VERSION 5.8 ;
BUSBITCHARS "[]" ;
DIVIDERCHAR "/" ;
UNITS
    DATABASE MICRONS 1000 ;
END UNITS

VIA ino_fetch_via1_2_1000_440_1_2_410_410
  VIARULE via1Array ;
  CUTSIZE 0.19 0.19 ;
  LAYERS Metal1 Via1 Metal2 ;
  CUTSPACING 0.22 0.22 ;
  ENCLOSURE 0.05 0.125 0.005 0.05 ;
  ROWCOL 1 2 ;
END ino_fetch_via1_2_1000_440_1_2_410_410

VIA ino_fetch_via2_3_1000_440_1_2_410_410
  VIARULE via2Array ;
  CUTSIZE 0.19 0.19 ;
  LAYERS Metal2 Via2 Metal3 ;
  CUTSPACING 0.22 0.22 ;
  ENCLOSURE 0.005 0.05 0.05 0.005 ;
  ROWCOL 1 2 ;
END ino_fetch_via2_3_1000_440_1_2_410_410

VIA ino_fetch_via3_4_1000_440_1_2_410_410
  VIARULE via3Array ;
  CUTSIZE 0.19 0.19 ;
  LAYERS Metal3 Via3 Metal4 ;
  CUTSPACING 0.22 0.22 ;
  ENCLOSURE 0.05 0.005 0.2 0.05 ;
  ROWCOL 1 2 ;
END ino_fetch_via3_4_1000_440_1_2_410_410

VIA ino_fetch_via4_5_1000_2000_1_1_840_840
  VIARULE viaTop1Array ;
  CUTSIZE 0.42 0.42 ;
  LAYERS Metal4 TopVia1 TopMetal1 ;
  CUTSPACING 0.42 0.42 ;
  ENCLOSURE 0.29 0.1 0.42 0.79 ;
END ino_fetch_via4_5_1000_2000_1_1_840_840

VIA ino_fetch_via4_5_1000_1640_1_1_840_840
  VIARULE viaTop1Array ;
  CUTSIZE 0.42 0.42 ;
  LAYERS Metal4 TopVia1 TopMetal1 ;
  CUTSPACING 0.42 0.42 ;
  ENCLOSURE 0.29 0.1 0.42 0.61 ;
END ino_fetch_via4_5_1000_1640_1_1_840_840

VIA ino_fetch_via4_5_1000_1400_1_1_840_840
  VIARULE viaTop1Array ;
  CUTSIZE 0.42 0.42 ;
  LAYERS Metal4 TopVia1 TopMetal1 ;
  CUTSPACING 0.42 0.42 ;
  ENCLOSURE 0.29 0.1 0.42 0.49 ;
END ino_fetch_via4_5_1000_1400_1_1_840_840

VIA ino_fetch_via4_5_4420_2000_1_4_840_840
  VIARULE viaTop1Array ;
  CUTSIZE 0.42 0.42 ;
  LAYERS Metal4 TopVia1 TopMetal1 ;
  CUTSPACING 0.42 0.42 ;
  ENCLOSURE 0.74 0.79 0.42 0.79 ;
  ROWCOL 1 4 ;
END ino_fetch_via4_5_4420_2000_1_4_840_840

VIA ino_fetch_via4_5_2810_2000_1_2_840_840
  VIARULE viaTop1Array ;
  CUTSIZE 0.42 0.42 ;
  LAYERS Metal4 TopVia1 TopMetal1 ;
  CUTSPACING 0.42 0.42 ;
  ENCLOSURE 0.775 0.79 0.42 0.79 ;
  ROWCOL 1 2 ;
END ino_fetch_via4_5_2810_2000_1_2_840_840

VIA ino_fetch_via4_5_4420_1650_1_4_840_840
  VIARULE viaTop1Array ;
  CUTSIZE 0.42 0.42 ;
  LAYERS Metal4 TopVia1 TopMetal1 ;
  CUTSPACING 0.42 0.42 ;
  ENCLOSURE 0.74 0.615 0.42 0.615 ;
  ROWCOL 1 4 ;
END ino_fetch_via4_5_4420_1650_1_4_840_840

VIA ino_fetch_via4_5_2810_1650_1_2_840_840
  VIARULE viaTop1Array ;
  CUTSIZE 0.42 0.42 ;
  LAYERS Metal4 TopVia1 TopMetal1 ;
  CUTSPACING 0.42 0.42 ;
  ENCLOSURE 0.775 0.615 0.42 0.615 ;
  ROWCOL 1 2 ;
END ino_fetch_via4_5_2810_1650_1_2_840_840

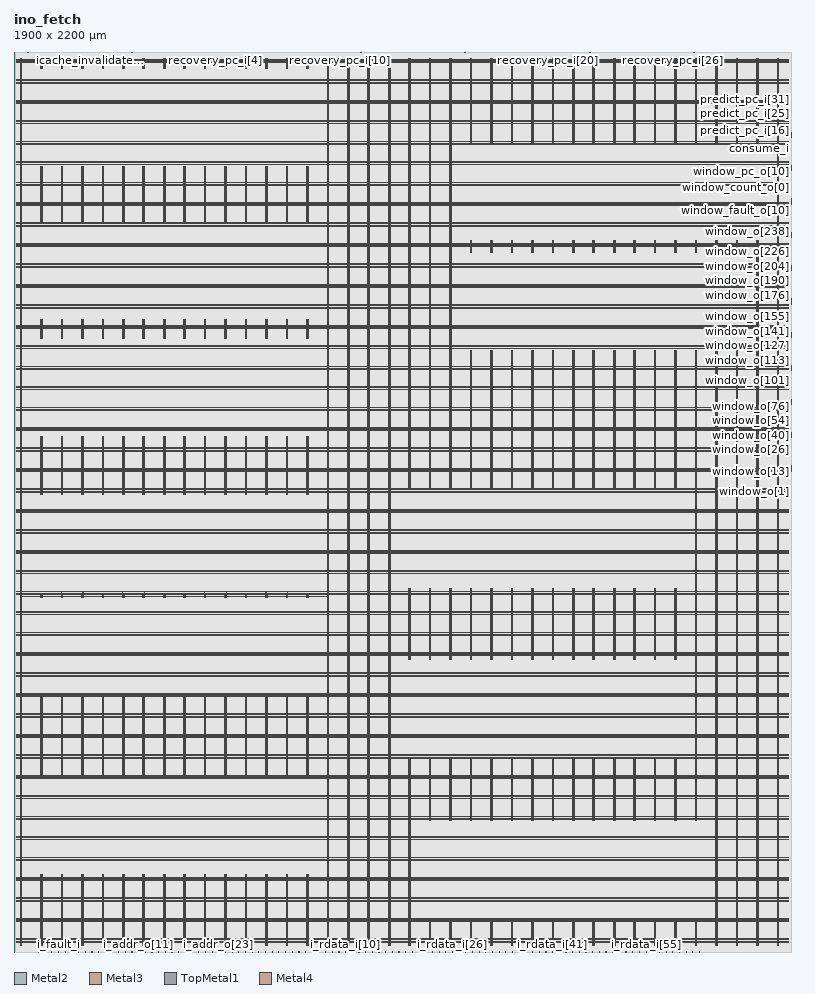
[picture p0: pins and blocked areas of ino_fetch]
MACRO ino_fetch
  FOREIGN ino_fetch 0 0 ;
  CLASS BLOCK ;
  SIZE 1900 BY 2200 ;
  PIN clk_i
    DIRECTION INPUT ;
    USE SIGNAL ;
    PORT
      LAYER Metal2 ;
        RECT  84.76 2199.6 85.16 2200 ;
    END
  END clk_i
  PIN consume_i
    DIRECTION INPUT ;
    USE SIGNAL ;
    PORT
      LAYER Metal3 ;
        RECT  1899.6 1964.14 1900 1964.54 ;
    END
  END consume_i
  PIN consumed_bytes_i[0]
    DIRECTION INPUT ;
    USE SIGNAL ;
    PORT
      LAYER Metal3 ;
        RECT  1899.6 1966.66 1900 1967.06 ;
    END
  END consumed_bytes_i[0]
  PIN consumed_bytes_i[1]
    DIRECTION INPUT ;
    USE SIGNAL ;
    PORT
      LAYER Metal3 ;
        RECT  1899.6 1969.18 1900 1969.58 ;
    END
  END consumed_bytes_i[1]
  PIN consumed_bytes_i[2]
    DIRECTION INPUT ;
    USE SIGNAL ;
    PORT
      LAYER Metal3 ;
        RECT  1899.6 1971.7 1900 1972.1 ;
    END
  END consumed_bytes_i[2]
  PIN consumed_bytes_i[3]
    DIRECTION INPUT ;
    USE SIGNAL ;
    PORT
      LAYER Metal3 ;
        RECT  1899.6 1974.22 1900 1974.62 ;
    END
  END consumed_bytes_i[3]
  PIN consumed_bytes_i[4]
    DIRECTION INPUT ;
    USE SIGNAL ;
    PORT
      LAYER Metal3 ;
        RECT  1899.6 1976.74 1900 1977.14 ;
    END
  END consumed_bytes_i[4]
  PIN consumed_bytes_i[5]
    DIRECTION INPUT ;
    USE SIGNAL ;
    PORT
      LAYER Metal3 ;
        RECT  1899.6 1979.26 1900 1979.66 ;
    END
  END consumed_bytes_i[5]
  PIN decode_stop_i
    DIRECTION INPUT ;
    USE SIGNAL ;
    PORT
      LAYER Metal3 ;
        RECT  1899.6 1981.78 1900 1982.18 ;
    END
  END decode_stop_i
  PIN halt_i
    DIRECTION INPUT ;
    USE SIGNAL ;
    PORT
      LAYER Metal2 ;
        RECT  135.64 2199.6 136.04 2200 ;
    END
  END halt_i
  PIN i_addr_o[0]
    DIRECTION OUTPUT ;
    USE SIGNAL ;
    PORT
      LAYER Metal2 ;
        RECT  125.08 0 125.48 0.4 ;
    END
  END i_addr_o[0]
  PIN i_addr_o[10]
    DIRECTION OUTPUT ;
    USE SIGNAL ;
    PORT
      LAYER Metal2 ;
        RECT  288.28 0 288.68 0.4 ;
    END
  END i_addr_o[10]
  PIN i_addr_o[11]
    DIRECTION OUTPUT ;
    USE SIGNAL ;
    PORT
      LAYER Metal2 ;
        RECT  304.6 0 305 0.4 ;
    END
  END i_addr_o[11]
  PIN i_addr_o[12]
    DIRECTION OUTPUT ;
    USE SIGNAL ;
    PORT
      LAYER Metal2 ;
        RECT  320.92 0 321.32 0.4 ;
    END
  END i_addr_o[12]
  PIN i_addr_o[13]
    DIRECTION OUTPUT ;
    USE SIGNAL ;
    PORT
      LAYER Metal2 ;
        RECT  337.24 0 337.64 0.4 ;
    END
  END i_addr_o[13]
  PIN i_addr_o[14]
    DIRECTION OUTPUT ;
    USE SIGNAL ;
    PORT
      LAYER Metal2 ;
        RECT  353.56 0 353.96 0.4 ;
    END
  END i_addr_o[14]
  PIN i_addr_o[15]
    DIRECTION OUTPUT ;
    USE SIGNAL ;
    PORT
      LAYER Metal2 ;
        RECT  369.88 0 370.28 0.4 ;
    END
  END i_addr_o[15]
  PIN i_addr_o[16]
    DIRECTION OUTPUT ;
    USE SIGNAL ;
    PORT
      LAYER Metal2 ;
        RECT  386.2 0 386.6 0.4 ;
    END
  END i_addr_o[16]
  PIN i_addr_o[17]
    DIRECTION OUTPUT ;
    USE SIGNAL ;
    PORT
      LAYER Metal2 ;
        RECT  402.52 0 402.92 0.4 ;
    END
  END i_addr_o[17]
  PIN i_addr_o[18]
    DIRECTION OUTPUT ;
    USE SIGNAL ;
    PORT
      LAYER Metal2 ;
        RECT  418.84 0 419.24 0.4 ;
    END
  END i_addr_o[18]
  PIN i_addr_o[19]
    DIRECTION OUTPUT ;
    USE SIGNAL ;
    PORT
      LAYER Metal2 ;
        RECT  435.16 0 435.56 0.4 ;
    END
  END i_addr_o[19]
  PIN i_addr_o[1]
    DIRECTION OUTPUT ;
    USE SIGNAL ;
    PORT
      LAYER Metal2 ;
        RECT  141.4 0 141.8 0.4 ;
    END
  END i_addr_o[1]
  PIN i_addr_o[20]
    DIRECTION OUTPUT ;
    USE SIGNAL ;
    PORT
      LAYER Metal2 ;
        RECT  451.48 0 451.88 0.4 ;
    END
  END i_addr_o[20]
  PIN i_addr_o[21]
    DIRECTION OUTPUT ;
    USE SIGNAL ;
    PORT
      LAYER Metal2 ;
        RECT  467.8 0 468.2 0.4 ;
    END
  END i_addr_o[21]
  PIN i_addr_o[22]
    DIRECTION OUTPUT ;
    USE SIGNAL ;
    PORT
      LAYER Metal2 ;
        RECT  484.12 0 484.52 0.4 ;
    END
  END i_addr_o[22]
  PIN i_addr_o[23]
    DIRECTION OUTPUT ;
    USE SIGNAL ;
    PORT
      LAYER Metal2 ;
        RECT  500.44 0 500.84 0.4 ;
    END
  END i_addr_o[23]
  PIN i_addr_o[24]
    DIRECTION OUTPUT ;
    USE SIGNAL ;
    PORT
      LAYER Metal2 ;
        RECT  516.76 0 517.16 0.4 ;
    END
  END i_addr_o[24]
  PIN i_addr_o[25]
    DIRECTION OUTPUT ;
    USE SIGNAL ;
    PORT
      LAYER Metal2 ;
        RECT  533.08 0 533.48 0.4 ;
    END
  END i_addr_o[25]
  PIN i_addr_o[26]
    DIRECTION OUTPUT ;
    USE SIGNAL ;
    PORT
      LAYER Metal2 ;
        RECT  549.4 0 549.8 0.4 ;
    END
  END i_addr_o[26]
  PIN i_addr_o[27]
    DIRECTION OUTPUT ;
    USE SIGNAL ;
    PORT
      LAYER Metal2 ;
        RECT  565.72 0 566.12 0.4 ;
    END
  END i_addr_o[27]
  PIN i_addr_o[28]
    DIRECTION OUTPUT ;
    USE SIGNAL ;
    PORT
      LAYER Metal2 ;
        RECT  582.04 0 582.44 0.4 ;
    END
  END i_addr_o[28]
  PIN i_addr_o[29]
    DIRECTION OUTPUT ;
    USE SIGNAL ;
    PORT
      LAYER Metal2 ;
        RECT  598.36 0 598.76 0.4 ;
    END
  END i_addr_o[29]
  PIN i_addr_o[2]
    DIRECTION OUTPUT ;
    USE SIGNAL ;
    PORT
      LAYER Metal2 ;
        RECT  157.72 0 158.12 0.4 ;
    END
  END i_addr_o[2]
  PIN i_addr_o[30]
    DIRECTION OUTPUT ;
    USE SIGNAL ;
    PORT
      LAYER Metal2 ;
        RECT  614.68 0 615.08 0.4 ;
    END
  END i_addr_o[30]
  PIN i_addr_o[31]
    DIRECTION OUTPUT ;
    USE SIGNAL ;
    PORT
      LAYER Metal2 ;
        RECT  631 0 631.4 0.4 ;
    END
  END i_addr_o[31]
  PIN i_addr_o[3]
    DIRECTION OUTPUT ;
    USE SIGNAL ;
    PORT
      LAYER Metal2 ;
        RECT  174.04 0 174.44 0.4 ;
    END
  END i_addr_o[3]
  PIN i_addr_o[4]
    DIRECTION OUTPUT ;
    USE SIGNAL ;
    PORT
      LAYER Metal2 ;
        RECT  190.36 0 190.76 0.4 ;
    END
  END i_addr_o[4]
  PIN i_addr_o[5]
    DIRECTION OUTPUT ;
    USE SIGNAL ;
    PORT
      LAYER Metal2 ;
        RECT  206.68 0 207.08 0.4 ;
    END
  END i_addr_o[5]
  PIN i_addr_o[6]
    DIRECTION OUTPUT ;
    USE SIGNAL ;
    PORT
      LAYER Metal2 ;
        RECT  223 0 223.4 0.4 ;
    END
  END i_addr_o[6]
  PIN i_addr_o[7]
    DIRECTION OUTPUT ;
    USE SIGNAL ;
    PORT
      LAYER Metal2 ;
        RECT  239.32 0 239.72 0.4 ;
    END
  END i_addr_o[7]
  PIN i_addr_o[8]
    DIRECTION OUTPUT ;
    USE SIGNAL ;
    PORT
      LAYER Metal2 ;
        RECT  255.64 0 256.04 0.4 ;
    END
  END i_addr_o[8]
  PIN i_addr_o[9]
    DIRECTION OUTPUT ;
    USE SIGNAL ;
    PORT
      LAYER Metal2 ;
        RECT  271.96 0 272.36 0.4 ;
    END
  END i_addr_o[9]
  PIN i_fault_i
    DIRECTION INPUT ;
    USE SIGNAL ;
    PORT
      LAYER Metal2 ;
        RECT  108.76 0 109.16 0.4 ;
    END
  END i_fault_i
  PIN i_rdata_i[0]
    DIRECTION INPUT ;
    USE SIGNAL ;
    PORT
      LAYER Metal2 ;
        RECT  647.32 0 647.72 0.4 ;
    END
  END i_rdata_i[0]
  PIN i_rdata_i[10]
    DIRECTION INPUT ;
    USE SIGNAL ;
    PORT
      LAYER Metal2 ;
        RECT  810.52 0 810.92 0.4 ;
    END
  END i_rdata_i[10]
  PIN i_rdata_i[11]
    DIRECTION INPUT ;
    USE SIGNAL ;
    PORT
      LAYER Metal2 ;
        RECT  826.84 0 827.24 0.4 ;
    END
  END i_rdata_i[11]
  PIN i_rdata_i[12]
    DIRECTION INPUT ;
    USE SIGNAL ;
    PORT
      LAYER Metal2 ;
        RECT  843.16 0 843.56 0.4 ;
    END
  END i_rdata_i[12]
  PIN i_rdata_i[13]
    DIRECTION INPUT ;
    USE SIGNAL ;
    PORT
      LAYER Metal2 ;
        RECT  859.48 0 859.88 0.4 ;
    END
  END i_rdata_i[13]
  PIN i_rdata_i[14]
    DIRECTION INPUT ;
    USE SIGNAL ;
    PORT
      LAYER Metal2 ;
        RECT  875.8 0 876.2 0.4 ;
    END
  END i_rdata_i[14]
  PIN i_rdata_i[15]
    DIRECTION INPUT ;
    USE SIGNAL ;
    PORT
      LAYER Metal2 ;
        RECT  892.12 0 892.52 0.4 ;
    END
  END i_rdata_i[15]
  PIN i_rdata_i[16]
    DIRECTION INPUT ;
    USE SIGNAL ;
    PORT
      LAYER Metal2 ;
        RECT  908.44 0 908.84 0.4 ;
    END
  END i_rdata_i[16]
  PIN i_rdata_i[17]
    DIRECTION INPUT ;
    USE SIGNAL ;
    PORT
      LAYER Metal2 ;
        RECT  924.76 0 925.16 0.4 ;
    END
  END i_rdata_i[17]
  PIN i_rdata_i[18]
    DIRECTION INPUT ;
    USE SIGNAL ;
    PORT
      LAYER Metal2 ;
        RECT  941.08 0 941.48 0.4 ;
    END
  END i_rdata_i[18]
  PIN i_rdata_i[19]
    DIRECTION INPUT ;
    USE SIGNAL ;
    PORT
      LAYER Metal2 ;
        RECT  957.4 0 957.8 0.4 ;
    END
  END i_rdata_i[19]
  PIN i_rdata_i[1]
    DIRECTION INPUT ;
    USE SIGNAL ;
    PORT
      LAYER Metal2 ;
        RECT  663.64 0 664.04 0.4 ;
    END
  END i_rdata_i[1]
  PIN i_rdata_i[20]
    DIRECTION INPUT ;
    USE SIGNAL ;
    PORT
      LAYER Metal2 ;
        RECT  973.72 0 974.12 0.4 ;
    END
  END i_rdata_i[20]
  PIN i_rdata_i[21]
    DIRECTION INPUT ;
    USE SIGNAL ;
    PORT
      LAYER Metal2 ;
        RECT  990.04 0 990.44 0.4 ;
    END
  END i_rdata_i[21]
  PIN i_rdata_i[22]
    DIRECTION INPUT ;
    USE SIGNAL ;
    PORT
      LAYER Metal2 ;
        RECT  1006.36 0 1006.76 0.4 ;
    END
  END i_rdata_i[22]
  PIN i_rdata_i[23]
    DIRECTION INPUT ;
    USE SIGNAL ;
    PORT
      LAYER Metal2 ;
        RECT  1022.68 0 1023.08 0.4 ;
    END
  END i_rdata_i[23]
  PIN i_rdata_i[24]
    DIRECTION INPUT ;
    USE SIGNAL ;
    PORT
      LAYER Metal2 ;
        RECT  1039 0 1039.4 0.4 ;
    END
  END i_rdata_i[24]
  PIN i_rdata_i[25]
    DIRECTION INPUT ;
    USE SIGNAL ;
    PORT
      LAYER Metal2 ;
        RECT  1055.32 0 1055.72 0.4 ;
    END
  END i_rdata_i[25]
  PIN i_rdata_i[26]
    DIRECTION INPUT ;
    USE SIGNAL ;
    PORT
      LAYER Metal2 ;
        RECT  1071.64 0 1072.04 0.4 ;
    END
  END i_rdata_i[26]
  PIN i_rdata_i[27]
    DIRECTION INPUT ;
    USE SIGNAL ;
    PORT
      LAYER Metal2 ;
        RECT  1087.96 0 1088.36 0.4 ;
    END
  END i_rdata_i[27]
  PIN i_rdata_i[28]
    DIRECTION INPUT ;
    USE SIGNAL ;
    PORT
      LAYER Metal2 ;
        RECT  1104.28 0 1104.68 0.4 ;
    END
  END i_rdata_i[28]
  PIN i_rdata_i[29]
    DIRECTION INPUT ;
    USE SIGNAL ;
    PORT
      LAYER Metal2 ;
        RECT  1120.6 0 1121 0.4 ;
    END
  END i_rdata_i[29]
  PIN i_rdata_i[2]
    DIRECTION INPUT ;
    USE SIGNAL ;
    PORT
      LAYER Metal2 ;
        RECT  679.96 0 680.36 0.4 ;
    END
  END i_rdata_i[2]
  PIN i_rdata_i[30]
    DIRECTION INPUT ;
    USE SIGNAL ;
    PORT
      LAYER Metal2 ;
        RECT  1136.92 0 1137.32 0.4 ;
    END
  END i_rdata_i[30]
  PIN i_rdata_i[31]
    DIRECTION INPUT ;
    USE SIGNAL ;
    PORT
      LAYER Metal2 ;
        RECT  1153.24 0 1153.64 0.4 ;
    END
  END i_rdata_i[31]
  PIN i_rdata_i[32]
    DIRECTION INPUT ;
    USE SIGNAL ;
    PORT
      LAYER Metal2 ;
        RECT  1169.56 0 1169.96 0.4 ;
    END
  END i_rdata_i[32]
  PIN i_rdata_i[33]
    DIRECTION INPUT ;
    USE SIGNAL ;
    PORT
      LAYER Metal2 ;
        RECT  1185.88 0 1186.28 0.4 ;
    END
  END i_rdata_i[33]
  PIN i_rdata_i[34]
    DIRECTION INPUT ;
    USE SIGNAL ;
    PORT
      LAYER Metal2 ;
        RECT  1202.2 0 1202.6 0.4 ;
    END
  END i_rdata_i[34]
  PIN i_rdata_i[35]
    DIRECTION INPUT ;
    USE SIGNAL ;
    PORT
      LAYER Metal2 ;
        RECT  1218.52 0 1218.92 0.4 ;
    END
  END i_rdata_i[35]
  PIN i_rdata_i[36]
    DIRECTION INPUT ;
    USE SIGNAL ;
    PORT
      LAYER Metal2 ;
        RECT  1234.84 0 1235.24 0.4 ;
    END
  END i_rdata_i[36]
  PIN i_rdata_i[37]
    DIRECTION INPUT ;
    USE SIGNAL ;
    PORT
      LAYER Metal2 ;
        RECT  1251.16 0 1251.56 0.4 ;
    END
  END i_rdata_i[37]
  PIN i_rdata_i[38]
    DIRECTION INPUT ;
    USE SIGNAL ;
    PORT
      LAYER Metal2 ;
        RECT  1267.48 0 1267.88 0.4 ;
    END
  END i_rdata_i[38]
  PIN i_rdata_i[39]
    DIRECTION INPUT ;
    USE SIGNAL ;
    PORT
      LAYER Metal2 ;
        RECT  1283.8 0 1284.2 0.4 ;
    END
  END i_rdata_i[39]
  PIN i_rdata_i[3]
    DIRECTION INPUT ;
    USE SIGNAL ;
    PORT
      LAYER Metal2 ;
        RECT  696.28 0 696.68 0.4 ;
    END
  END i_rdata_i[3]
  PIN i_rdata_i[40]
    DIRECTION INPUT ;
    USE SIGNAL ;
    PORT
      LAYER Metal2 ;
        RECT  1300.12 0 1300.52 0.4 ;
    END
  END i_rdata_i[40]
  PIN i_rdata_i[41]
    DIRECTION INPUT ;
    USE SIGNAL ;
    PORT
      LAYER Metal2 ;
        RECT  1316.44 0 1316.84 0.4 ;
    END
  END i_rdata_i[41]
  PIN i_rdata_i[42]
    DIRECTION INPUT ;
    USE SIGNAL ;
    PORT
      LAYER Metal2 ;
        RECT  1332.76 0 1333.16 0.4 ;
    END
  END i_rdata_i[42]
  PIN i_rdata_i[43]
    DIRECTION INPUT ;
    USE SIGNAL ;
    PORT
      LAYER Metal2 ;
        RECT  1349.08 0 1349.48 0.4 ;
    END
  END i_rdata_i[43]
  PIN i_rdata_i[44]
    DIRECTION INPUT ;
    USE SIGNAL ;
    PORT
      LAYER Metal2 ;
        RECT  1365.4 0 1365.8 0.4 ;
    END
  END i_rdata_i[44]
  PIN i_rdata_i[45]
    DIRECTION INPUT ;
    USE SIGNAL ;
    PORT
      LAYER Metal2 ;
        RECT  1381.72 0 1382.12 0.4 ;
    END
  END i_rdata_i[45]
  PIN i_rdata_i[46]
    DIRECTION INPUT ;
    USE SIGNAL ;
    PORT
      LAYER Metal2 ;
        RECT  1398.04 0 1398.44 0.4 ;
    END
  END i_rdata_i[46]
  PIN i_rdata_i[47]
    DIRECTION INPUT ;
    USE SIGNAL ;
    PORT
      LAYER Metal2 ;
        RECT  1414.36 0 1414.76 0.4 ;
    END
  END i_rdata_i[47]
  PIN i_rdata_i[48]
    DIRECTION INPUT ;
    USE SIGNAL ;
    PORT
      LAYER Metal2 ;
        RECT  1430.68 0 1431.08 0.4 ;
    END
  END i_rdata_i[48]
  PIN i_rdata_i[49]
    DIRECTION INPUT ;
    USE SIGNAL ;
    PORT
      LAYER Metal2 ;
        RECT  1447 0 1447.4 0.4 ;
    END
  END i_rdata_i[49]
  PIN i_rdata_i[4]
    DIRECTION INPUT ;
    USE SIGNAL ;
    PORT
      LAYER Metal2 ;
        RECT  712.6 0 713 0.4 ;
    END
  END i_rdata_i[4]
  PIN i_rdata_i[50]
    DIRECTION INPUT ;
    USE SIGNAL ;
    PORT
      LAYER Metal2 ;
        RECT  1463.32 0 1463.72 0.4 ;
    END
  END i_rdata_i[50]
  PIN i_rdata_i[51]
    DIRECTION INPUT ;
    USE SIGNAL ;
    PORT
      LAYER Metal2 ;
        RECT  1479.64 0 1480.04 0.4 ;
    END
  END i_rdata_i[51]
  PIN i_rdata_i[52]
    DIRECTION INPUT ;
    USE SIGNAL ;
    PORT
      LAYER Metal2 ;
        RECT  1495.96 0 1496.36 0.4 ;
    END
  END i_rdata_i[52]
  PIN i_rdata_i[53]
    DIRECTION INPUT ;
    USE SIGNAL ;
    PORT
      LAYER Metal2 ;
        RECT  1512.28 0 1512.68 0.4 ;
    END
  END i_rdata_i[53]
  PIN i_rdata_i[54]
    DIRECTION INPUT ;
    USE SIGNAL ;
    PORT
      LAYER Metal2 ;
        RECT  1528.6 0 1529 0.4 ;
    END
  END i_rdata_i[54]
  PIN i_rdata_i[55]
    DIRECTION INPUT ;
    USE SIGNAL ;
    PORT
      LAYER Metal2 ;
        RECT  1544.92 0 1545.32 0.4 ;
    END
  END i_rdata_i[55]
  PIN i_rdata_i[56]
    DIRECTION INPUT ;
    USE SIGNAL ;
    PORT
      LAYER Metal2 ;
        RECT  1561.24 0 1561.64 0.4 ;
    END
  END i_rdata_i[56]
  PIN i_rdata_i[57]
    DIRECTION INPUT ;
    USE SIGNAL ;
    PORT
      LAYER Metal2 ;
        RECT  1577.56 0 1577.96 0.4 ;
    END
  END i_rdata_i[57]
  PIN i_rdata_i[58]
    DIRECTION INPUT ;
    USE SIGNAL ;
    PORT
      LAYER Metal2 ;
        RECT  1593.88 0 1594.28 0.4 ;
    END
  END i_rdata_i[58]
  PIN i_rdata_i[59]
    DIRECTION INPUT ;
    USE SIGNAL ;
    PORT
      LAYER Metal2 ;
        RECT  1610.2 0 1610.6 0.4 ;
    END
  END i_rdata_i[59]
  PIN i_rdata_i[5]
    DIRECTION INPUT ;
    USE SIGNAL ;
    PORT
      LAYER Metal2 ;
        RECT  728.92 0 729.32 0.4 ;
    END
  END i_rdata_i[5]
  PIN i_rdata_i[60]
    DIRECTION INPUT ;
    USE SIGNAL ;
    PORT
      LAYER Metal2 ;
        RECT  1626.52 0 1626.92 0.4 ;
    END
  END i_rdata_i[60]
  PIN i_rdata_i[61]
    DIRECTION INPUT ;
    USE SIGNAL ;
    PORT
      LAYER Metal2 ;
        RECT  1642.84 0 1643.24 0.4 ;
    END
  END i_rdata_i[61]
  PIN i_rdata_i[62]
    DIRECTION INPUT ;
    USE SIGNAL ;
    PORT
      LAYER Metal2 ;
        RECT  1659.16 0 1659.56 0.4 ;
    END
  END i_rdata_i[62]
  PIN i_rdata_i[63]
    DIRECTION INPUT ;
    USE SIGNAL ;
    PORT
      LAYER Metal2 ;
        RECT  1675.48 0 1675.88 0.4 ;
    END
  END i_rdata_i[63]
  PIN i_rdata_i[6]
    DIRECTION INPUT ;
    USE SIGNAL ;
    PORT
      LAYER Metal2 ;
        RECT  745.24 0 745.64 0.4 ;
    END
  END i_rdata_i[6]
  PIN i_rdata_i[7]
    DIRECTION INPUT ;
    USE SIGNAL ;
    PORT
      LAYER Metal2 ;
        RECT  761.56 0 761.96 0.4 ;
    END
  END i_rdata_i[7]
  PIN i_rdata_i[8]
    DIRECTION INPUT ;
    USE SIGNAL ;
    PORT
      LAYER Metal2 ;
        RECT  777.88 0 778.28 0.4 ;
    END
  END i_rdata_i[8]
  PIN i_rdata_i[9]
    DIRECTION INPUT ;
    USE SIGNAL ;
    PORT
      LAYER Metal2 ;
        RECT  794.2 0 794.6 0.4 ;
    END
  END i_rdata_i[9]
  PIN i_ready_i
    DIRECTION INPUT ;
    USE SIGNAL ;
    PORT
      LAYER Metal2 ;
        RECT  76.12 0 76.52 0.4 ;
    END
  END i_ready_i
  PIN i_req_o
    DIRECTION OUTPUT ;
    USE SIGNAL ;
    PORT
      LAYER Metal2 ;
        RECT  59.8 0 60.2 0.4 ;
    END
  END i_req_o
  PIN i_rvalid_i
    DIRECTION INPUT ;
    USE SIGNAL ;
    PORT
      LAYER Metal2 ;
        RECT  92.44 0 92.84 0.4 ;
    END
  END i_rvalid_i
  PIN icache_invalidate_i
    DIRECTION INPUT ;
    USE SIGNAL ;
    PORT
      LAYER Metal2 ;
        RECT  186.52 2199.6 186.92 2200 ;
    END
  END icache_invalidate_i
  PIN predict_pc_i[0]
    DIRECTION INPUT ;
    USE SIGNAL ;
    PORT
      LAYER Metal3 ;
        RECT  1899.6 1986.82 1900 1987.22 ;
    END
  END predict_pc_i[0]
  PIN predict_pc_i[10]
    DIRECTION INPUT ;
    USE SIGNAL ;
    PORT
      LAYER Metal3 ;
        RECT  1899.6 2012.02 1900 2012.42 ;
    END
  END predict_pc_i[10]
  PIN predict_pc_i[11]
    DIRECTION INPUT ;
    USE SIGNAL ;
    PORT
      LAYER Metal3 ;
        RECT  1899.6 2014.54 1900 2014.94 ;
    END
  END predict_pc_i[11]
  PIN predict_pc_i[12]
    DIRECTION INPUT ;
    USE SIGNAL ;
    PORT
      LAYER Metal3 ;
        RECT  1899.6 2017.06 1900 2017.46 ;
    END
  END predict_pc_i[12]
  PIN predict_pc_i[13]
    DIRECTION INPUT ;
    USE SIGNAL ;
    PORT
      LAYER Metal3 ;
        RECT  1899.6 2019.58 1900 2019.98 ;
    END
  END predict_pc_i[13]
  PIN predict_pc_i[14]
    DIRECTION INPUT ;
    USE SIGNAL ;
    PORT
      LAYER Metal3 ;
        RECT  1899.6 2022.1 1900 2022.5 ;
    END
  END predict_pc_i[14]
  PIN predict_pc_i[15]
    DIRECTION INPUT ;
    USE SIGNAL ;
    PORT
      LAYER Metal3 ;
        RECT  1899.6 2024.62 1900 2025.02 ;
    END
  END predict_pc_i[15]
  PIN predict_pc_i[16]
    DIRECTION INPUT ;
    USE SIGNAL ;
    PORT
      LAYER Metal3 ;
        RECT  1899.6 2027.14 1900 2027.54 ;
    END
  END predict_pc_i[16]
  PIN predict_pc_i[17]
    DIRECTION INPUT ;
    USE SIGNAL ;
    PORT
      LAYER Metal3 ;
        RECT  1899.6 2029.66 1900 2030.06 ;
    END
  END predict_pc_i[17]
  PIN predict_pc_i[18]
    DIRECTION INPUT ;
    USE SIGNAL ;
    PORT
      LAYER Metal3 ;
        RECT  1899.6 2032.18 1900 2032.58 ;
    END
  END predict_pc_i[18]
  PIN predict_pc_i[19]
    DIRECTION INPUT ;
    USE SIGNAL ;
    PORT
      LAYER Metal3 ;
        RECT  1899.6 2034.7 1900 2035.1 ;
    END
  END predict_pc_i[19]
  PIN predict_pc_i[1]
    DIRECTION INPUT ;
    USE SIGNAL ;
    PORT
      LAYER Metal3 ;
        RECT  1899.6 1989.34 1900 1989.74 ;
    END
  END predict_pc_i[1]
  PIN predict_pc_i[20]
    DIRECTION INPUT ;
    USE SIGNAL ;
    PORT
      LAYER Metal3 ;
        RECT  1899.6 2037.22 1900 2037.62 ;
    END
  END predict_pc_i[20]
  PIN predict_pc_i[21]
    DIRECTION INPUT ;
    USE SIGNAL ;
    PORT
      LAYER Metal3 ;
        RECT  1899.6 2039.74 1900 2040.14 ;
    END
  END predict_pc_i[21]
  PIN predict_pc_i[22]
    DIRECTION INPUT ;
    USE SIGNAL ;
    PORT
      LAYER Metal3 ;
        RECT  1899.6 2042.26 1900 2042.66 ;
    END
  END predict_pc_i[22]
  PIN predict_pc_i[23]
    DIRECTION INPUT ;
    USE SIGNAL ;
    PORT
      LAYER Metal3 ;
        RECT  1899.6 2044.78 1900 2045.18 ;
    END
  END predict_pc_i[23]
  PIN predict_pc_i[24]
    DIRECTION INPUT ;
    USE SIGNAL ;
    PORT
      LAYER Metal3 ;
        RECT  1899.6 2047.3 1900 2047.7 ;
    END
  END predict_pc_i[24]
  PIN predict_pc_i[25]
    DIRECTION INPUT ;
    USE SIGNAL ;
    PORT
      LAYER Metal3 ;
        RECT  1899.6 2049.82 1900 2050.22 ;
    END
  END predict_pc_i[25]
  PIN predict_pc_i[26]
    DIRECTION INPUT ;
    USE SIGNAL ;
    PORT
      LAYER Metal3 ;
        RECT  1899.6 2052.34 1900 2052.74 ;
    END
  END predict_pc_i[26]
  PIN predict_pc_i[27]
    DIRECTION INPUT ;
    USE SIGNAL ;
    PORT
      LAYER Metal3 ;
        RECT  1899.6 2054.86 1900 2055.26 ;
    END
  END predict_pc_i[27]
  PIN predict_pc_i[28]
    DIRECTION INPUT ;
    USE SIGNAL ;
    PORT
      LAYER Metal3 ;
        RECT  1899.6 2057.38 1900 2057.78 ;
    END
  END predict_pc_i[28]
  PIN predict_pc_i[29]
    DIRECTION INPUT ;
    USE SIGNAL ;
    PORT
      LAYER Metal3 ;
        RECT  1899.6 2059.9 1900 2060.3 ;
    END
  END predict_pc_i[29]
  PIN predict_pc_i[2]
    DIRECTION INPUT ;
    USE SIGNAL ;
    PORT
      LAYER Metal3 ;
        RECT  1899.6 1991.86 1900 1992.26 ;
    END
  END predict_pc_i[2]
  PIN predict_pc_i[30]
    DIRECTION INPUT ;
    USE SIGNAL ;
    PORT
      LAYER Metal3 ;
        RECT  1899.6 2062.42 1900 2062.82 ;
    END
  END predict_pc_i[30]
  PIN predict_pc_i[31]
    DIRECTION INPUT ;
    USE SIGNAL ;
    PORT
      LAYER Metal3 ;
        RECT  1899.6 2064.94 1900 2065.34 ;
    END
  END predict_pc_i[31]
  PIN predict_pc_i[3]
    DIRECTION INPUT ;
    USE SIGNAL ;
    PORT
      LAYER Metal3 ;
        RECT  1899.6 1994.38 1900 1994.78 ;
    END
  END predict_pc_i[3]
  PIN predict_pc_i[4]
    DIRECTION INPUT ;
    USE SIGNAL ;
    PORT
      LAYER Metal3 ;
        RECT  1899.6 1996.9 1900 1997.3 ;
    END
  END predict_pc_i[4]
  PIN predict_pc_i[5]
    DIRECTION INPUT ;
    USE SIGNAL ;
    PORT
      LAYER Metal3 ;
        RECT  1899.6 1999.42 1900 1999.82 ;
    END
  END predict_pc_i[5]
  PIN predict_pc_i[6]
    DIRECTION INPUT ;
    USE SIGNAL ;
    PORT
      LAYER Metal3 ;
        RECT  1899.6 2001.94 1900 2002.34 ;
    END
  END predict_pc_i[6]
  PIN predict_pc_i[7]
    DIRECTION INPUT ;
    USE SIGNAL ;
    PORT
      LAYER Metal3 ;
        RECT  1899.6 2004.46 1900 2004.86 ;
    END
  END predict_pc_i[7]
  PIN predict_pc_i[8]
    DIRECTION INPUT ;
    USE SIGNAL ;
    PORT
      LAYER Metal3 ;
        RECT  1899.6 2006.98 1900 2007.38 ;
    END
  END predict_pc_i[8]
  PIN predict_pc_i[9]
    DIRECTION INPUT ;
    USE SIGNAL ;
    PORT
      LAYER Metal3 ;
        RECT  1899.6 2009.5 1900 2009.9 ;
    END
  END predict_pc_i[9]
  PIN predict_valid_i
    DIRECTION INPUT ;
    USE SIGNAL ;
    PORT
      LAYER Metal3 ;
        RECT  1899.6 1984.3 1900 1984.7 ;
    END
  END predict_valid_i
  PIN recovery_pc_i[0]
    DIRECTION INPUT ;
    USE SIGNAL ;
    PORT
      LAYER Metal2 ;
        RECT  288.28 2199.6 288.68 2200 ;
    END
  END recovery_pc_i[0]
  PIN recovery_pc_i[10]
    DIRECTION INPUT ;
    USE SIGNAL ;
    PORT
      LAYER Metal2 ;
        RECT  797.08 2199.6 797.48 2200 ;
    END
  END recovery_pc_i[10]
  PIN recovery_pc_i[11]
    DIRECTION INPUT ;
    USE SIGNAL ;
    PORT
      LAYER Metal2 ;
        RECT  847.96 2199.6 848.36 2200 ;
    END
  END recovery_pc_i[11]
  PIN recovery_pc_i[12]
    DIRECTION INPUT ;
    USE SIGNAL ;
    PORT
      LAYER Metal2 ;
        RECT  898.84 2199.6 899.24 2200 ;
    END
  END recovery_pc_i[12]
  PIN recovery_pc_i[13]
    DIRECTION INPUT ;
    USE SIGNAL ;
    PORT
      LAYER Metal2 ;
        RECT  949.72 2199.6 950.12 2200 ;
    END
  END recovery_pc_i[13]
  PIN recovery_pc_i[14]
    DIRECTION INPUT ;
    USE SIGNAL ;
    PORT
      LAYER Metal2 ;
        RECT  1000.6 2199.6 1001 2200 ;
    END
  END recovery_pc_i[14]
  PIN recovery_pc_i[15]
    DIRECTION INPUT ;
    USE SIGNAL ;
    PORT
      LAYER Metal2 ;
        RECT  1051.48 2199.6 1051.88 2200 ;
    END
  END recovery_pc_i[15]
  PIN recovery_pc_i[16]
    DIRECTION INPUT ;
    USE SIGNAL ;
    PORT
      LAYER Metal2 ;
        RECT  1102.36 2199.6 1102.76 2200 ;
    END
  END recovery_pc_i[16]
  PIN recovery_pc_i[17]
    DIRECTION INPUT ;
    USE SIGNAL ;
    PORT
      LAYER Metal2 ;
        RECT  1153.24 2199.6 1153.64 2200 ;
    END
  END recovery_pc_i[17]
  PIN recovery_pc_i[18]
    DIRECTION INPUT ;
    USE SIGNAL ;
    PORT
      LAYER Metal2 ;
        RECT  1204.12 2199.6 1204.52 2200 ;
    END
  END recovery_pc_i[18]
  PIN recovery_pc_i[19]
    DIRECTION INPUT ;
    USE SIGNAL ;
    PORT
      LAYER Metal2 ;
        RECT  1255 2199.6 1255.4 2200 ;
    END
  END recovery_pc_i[19]
  PIN recovery_pc_i[1]
    DIRECTION INPUT ;
    USE SIGNAL ;
    PORT
      LAYER Metal2 ;
        RECT  339.16 2199.6 339.56 2200 ;
    END
  END recovery_pc_i[1]
  PIN recovery_pc_i[20]
    DIRECTION INPUT ;
    USE SIGNAL ;
    PORT
      LAYER Metal2 ;
        RECT  1305.88 2199.6 1306.28 2200 ;
    END
  END recovery_pc_i[20]
  PIN recovery_pc_i[21]
    DIRECTION INPUT ;
    USE SIGNAL ;
    PORT
      LAYER Metal2 ;
        RECT  1356.76 2199.6 1357.16 2200 ;
    END
  END recovery_pc_i[21]
  PIN recovery_pc_i[22]
    DIRECTION INPUT ;
    USE SIGNAL ;
    PORT
      LAYER Metal2 ;
        RECT  1407.64 2199.6 1408.04 2200 ;
    END
  END recovery_pc_i[22]
  PIN recovery_pc_i[23]
    DIRECTION INPUT ;
    USE SIGNAL ;
    PORT
      LAYER Metal2 ;
        RECT  1458.52 2199.6 1458.92 2200 ;
    END
  END recovery_pc_i[23]
  PIN recovery_pc_i[24]
    DIRECTION INPUT ;
    USE SIGNAL ;
    PORT
      LAYER Metal2 ;
        RECT  1509.4 2199.6 1509.8 2200 ;
    END
  END recovery_pc_i[24]
  PIN recovery_pc_i[25]
    DIRECTION INPUT ;
    USE SIGNAL ;
    PORT
      LAYER Metal2 ;
        RECT  1560.28 2199.6 1560.68 2200 ;
    END
  END recovery_pc_i[25]
  PIN recovery_pc_i[26]
    DIRECTION INPUT ;
    USE SIGNAL ;
    PORT
      LAYER Metal2 ;
        RECT  1611.16 2199.6 1611.56 2200 ;
    END
  END recovery_pc_i[26]
  PIN recovery_pc_i[27]
    DIRECTION INPUT ;
    USE SIGNAL ;
    PORT
      LAYER Metal2 ;
        RECT  1662.04 2199.6 1662.44 2200 ;
    END
  END recovery_pc_i[27]
  PIN recovery_pc_i[28]
    DIRECTION INPUT ;
    USE SIGNAL ;
    PORT
      LAYER Metal2 ;
        RECT  1712.92 2199.6 1713.32 2200 ;
    END
  END recovery_pc_i[28]
  PIN recovery_pc_i[29]
    DIRECTION INPUT ;
    USE SIGNAL ;
    PORT
      LAYER Metal2 ;
        RECT  1763.8 2199.6 1764.2 2200 ;
    END
  END recovery_pc_i[29]
  PIN recovery_pc_i[2]
    DIRECTION INPUT ;
    USE SIGNAL ;
    PORT
      LAYER Metal2 ;
        RECT  390.04 2199.6 390.44 2200 ;
    END
  END recovery_pc_i[2]
  PIN recovery_pc_i[30]
    DIRECTION INPUT ;
    USE SIGNAL ;
    PORT
      LAYER Metal2 ;
        RECT  1814.68 2199.6 1815.08 2200 ;
    END
  END recovery_pc_i[30]
  PIN recovery_pc_i[31]
    DIRECTION INPUT ;
    USE SIGNAL ;
    PORT
      LAYER Metal2 ;
        RECT  1865.56 2199.6 1865.96 2200 ;
    END
  END recovery_pc_i[31]
  PIN recovery_pc_i[3]
    DIRECTION INPUT ;
    USE SIGNAL ;
    PORT
      LAYER Metal2 ;
        RECT  440.92 2199.6 441.32 2200 ;
    END
  END recovery_pc_i[3]
  PIN recovery_pc_i[4]
    DIRECTION INPUT ;
    USE SIGNAL ;
    PORT
      LAYER Metal2 ;
        RECT  491.8 2199.6 492.2 2200 ;
    END
  END recovery_pc_i[4]
  PIN recovery_pc_i[5]
    DIRECTION INPUT ;
    USE SIGNAL ;
    PORT
      LAYER Metal2 ;
        RECT  542.68 2199.6 543.08 2200 ;
    END
  END recovery_pc_i[5]
  PIN recovery_pc_i[6]
    DIRECTION INPUT ;
    USE SIGNAL ;
    PORT
      LAYER Metal2 ;
        RECT  593.56 2199.6 593.96 2200 ;
    END
  END recovery_pc_i[6]
  PIN recovery_pc_i[7]
    DIRECTION INPUT ;
    USE SIGNAL ;
    PORT
      LAYER Metal2 ;
        RECT  644.44 2199.6 644.84 2200 ;
    END
  END recovery_pc_i[7]
  PIN recovery_pc_i[8]
    DIRECTION INPUT ;
    USE SIGNAL ;
    PORT
      LAYER Metal2 ;
        RECT  695.32 2199.6 695.72 2200 ;
    END
  END recovery_pc_i[8]
  PIN recovery_pc_i[9]
    DIRECTION INPUT ;
    USE SIGNAL ;
    PORT
      LAYER Metal2 ;
        RECT  746.2 2199.6 746.6 2200 ;
    END
  END recovery_pc_i[9]
  PIN recovery_valid_i
    DIRECTION INPUT ;
    USE SIGNAL ;
    PORT
      LAYER Metal2 ;
        RECT  237.4 2199.6 237.8 2200 ;
    END
  END recovery_valid_i
  PIN reset_i
    DIRECTION INPUT ;
    USE SIGNAL ;
    PORT
      LAYER Metal2 ;
        RECT  33.88 2199.6 34.28 2200 ;
    END
  END reset_i
  PIN window_count_o[0]
    DIRECTION OUTPUT ;
    USE SIGNAL ;
    PORT
      LAYER Metal3 ;
        RECT  1899.6 1868.38 1900 1868.78 ;
    END
  END window_count_o[0]
  PIN window_count_o[1]
    DIRECTION OUTPUT ;
    USE SIGNAL ;
    PORT
      LAYER Metal3 ;
        RECT  1899.6 1870.9 1900 1871.3 ;
    END
  END window_count_o[1]
  PIN window_count_o[2]
    DIRECTION OUTPUT ;
    USE SIGNAL ;
    PORT
      LAYER Metal3 ;
        RECT  1899.6 1873.42 1900 1873.82 ;
    END
  END window_count_o[2]
  PIN window_count_o[3]
    DIRECTION OUTPUT ;
    USE SIGNAL ;
    PORT
      LAYER Metal3 ;
        RECT  1899.6 1875.94 1900 1876.34 ;
    END
  END window_count_o[3]
  PIN window_count_o[4]
    DIRECTION OUTPUT ;
    USE SIGNAL ;
    PORT
      LAYER Metal3 ;
        RECT  1899.6 1878.46 1900 1878.86 ;
    END
  END window_count_o[4]
  PIN window_count_o[5]
    DIRECTION OUTPUT ;
    USE SIGNAL ;
    PORT
      LAYER Metal3 ;
        RECT  1899.6 1880.98 1900 1881.38 ;
    END
  END window_count_o[5]
  PIN window_fault_o[0]
    DIRECTION OUTPUT ;
    USE SIGNAL ;
    PORT
      LAYER Metal3 ;
        RECT  1899.6 1787.74 1900 1788.14 ;
    END
  END window_fault_o[0]
  PIN window_fault_o[10]
    DIRECTION OUTPUT ;
    USE SIGNAL ;
    PORT
      LAYER Metal3 ;
        RECT  1899.6 1812.94 1900 1813.34 ;
    END
  END window_fault_o[10]
  PIN window_fault_o[11]
    DIRECTION OUTPUT ;
    USE SIGNAL ;
    PORT
      LAYER Metal3 ;
        RECT  1899.6 1815.46 1900 1815.86 ;
    END
  END window_fault_o[11]
  PIN window_fault_o[12]
    DIRECTION OUTPUT ;
    USE SIGNAL ;
    PORT
      LAYER Metal3 ;
        RECT  1899.6 1817.98 1900 1818.38 ;
    END
  END window_fault_o[12]
  PIN window_fault_o[13]
    DIRECTION OUTPUT ;
    USE SIGNAL ;
    PORT
      LAYER Metal3 ;
        RECT  1899.6 1820.5 1900 1820.9 ;
    END
  END window_fault_o[13]
  PIN window_fault_o[14]
    DIRECTION OUTPUT ;
    USE SIGNAL ;
    PORT
      LAYER Metal3 ;
        RECT  1899.6 1823.02 1900 1823.42 ;
    END
  END window_fault_o[14]
  PIN window_fault_o[15]
    DIRECTION OUTPUT ;
    USE SIGNAL ;
    PORT
      LAYER Metal3 ;
        RECT  1899.6 1825.54 1900 1825.94 ;
    END
  END window_fault_o[15]
  PIN window_fault_o[16]
    DIRECTION OUTPUT ;
    USE SIGNAL ;
    PORT
      LAYER Metal3 ;
        RECT  1899.6 1828.06 1900 1828.46 ;
    END
  END window_fault_o[16]
  PIN window_fault_o[17]
    DIRECTION OUTPUT ;
    USE SIGNAL ;
    PORT
      LAYER Metal3 ;
        RECT  1899.6 1830.58 1900 1830.98 ;
    END
  END window_fault_o[17]
  PIN window_fault_o[18]
    DIRECTION OUTPUT ;
    USE SIGNAL ;
    PORT
      LAYER Metal3 ;
        RECT  1899.6 1833.1 1900 1833.5 ;
    END
  END window_fault_o[18]
  PIN window_fault_o[19]
    DIRECTION OUTPUT ;
    USE SIGNAL ;
    PORT
      LAYER Metal3 ;
        RECT  1899.6 1835.62 1900 1836.02 ;
    END
  END window_fault_o[19]
  PIN window_fault_o[1]
    DIRECTION OUTPUT ;
    USE SIGNAL ;
    PORT
      LAYER Metal3 ;
        RECT  1899.6 1790.26 1900 1790.66 ;
    END
  END window_fault_o[1]
  PIN window_fault_o[20]
    DIRECTION OUTPUT ;
    USE SIGNAL ;
    PORT
      LAYER Metal3 ;
        RECT  1899.6 1838.14 1900 1838.54 ;
    END
  END window_fault_o[20]
  PIN window_fault_o[21]
    DIRECTION OUTPUT ;
    USE SIGNAL ;
    PORT
      LAYER Metal3 ;
        RECT  1899.6 1840.66 1900 1841.06 ;
    END
  END window_fault_o[21]
  PIN window_fault_o[22]
    DIRECTION OUTPUT ;
    USE SIGNAL ;
    PORT
      LAYER Metal3 ;
        RECT  1899.6 1843.18 1900 1843.58 ;
    END
  END window_fault_o[22]
  PIN window_fault_o[23]
    DIRECTION OUTPUT ;
    USE SIGNAL ;
    PORT
      LAYER Metal3 ;
        RECT  1899.6 1845.7 1900 1846.1 ;
    END
  END window_fault_o[23]
  PIN window_fault_o[24]
    DIRECTION OUTPUT ;
    USE SIGNAL ;
    PORT
      LAYER Metal3 ;
        RECT  1899.6 1848.22 1900 1848.62 ;
    END
  END window_fault_o[24]
  PIN window_fault_o[25]
    DIRECTION OUTPUT ;
    USE SIGNAL ;
    PORT
      LAYER Metal3 ;
        RECT  1899.6 1850.74 1900 1851.14 ;
    END
  END window_fault_o[25]
  PIN window_fault_o[26]
    DIRECTION OUTPUT ;
    USE SIGNAL ;
    PORT
      LAYER Metal3 ;
        RECT  1899.6 1853.26 1900 1853.66 ;
    END
  END window_fault_o[26]
  PIN window_fault_o[27]
    DIRECTION OUTPUT ;
    USE SIGNAL ;
    PORT
      LAYER Metal3 ;
        RECT  1899.6 1855.78 1900 1856.18 ;
    END
  END window_fault_o[27]
  PIN window_fault_o[28]
    DIRECTION OUTPUT ;
    USE SIGNAL ;
    PORT
      LAYER Metal3 ;
        RECT  1899.6 1858.3 1900 1858.7 ;
    END
  END window_fault_o[28]
  PIN window_fault_o[29]
    DIRECTION OUTPUT ;
    USE SIGNAL ;
    PORT
      LAYER Metal3 ;
        RECT  1899.6 1860.82 1900 1861.22 ;
    END
  END window_fault_o[29]
  PIN window_fault_o[2]
    DIRECTION OUTPUT ;
    USE SIGNAL ;
    PORT
      LAYER Metal3 ;
        RECT  1899.6 1792.78 1900 1793.18 ;
    END
  END window_fault_o[2]
  PIN window_fault_o[30]
    DIRECTION OUTPUT ;
    USE SIGNAL ;
    PORT
      LAYER Metal3 ;
        RECT  1899.6 1863.34 1900 1863.74 ;
    END
  END window_fault_o[30]
  PIN window_fault_o[31]
    DIRECTION OUTPUT ;
    USE SIGNAL ;
    PORT
      LAYER Metal3 ;
        RECT  1899.6 1865.86 1900 1866.26 ;
    END
  END window_fault_o[31]
  PIN window_fault_o[3]
    DIRECTION OUTPUT ;
    USE SIGNAL ;
    PORT
      LAYER Metal3 ;
        RECT  1899.6 1795.3 1900 1795.7 ;
    END
  END window_fault_o[3]
  PIN window_fault_o[4]
    DIRECTION OUTPUT ;
    USE SIGNAL ;
    PORT
      LAYER Metal3 ;
        RECT  1899.6 1797.82 1900 1798.22 ;
    END
  END window_fault_o[4]
  PIN window_fault_o[5]
    DIRECTION OUTPUT ;
    USE SIGNAL ;
    PORT
      LAYER Metal3 ;
        RECT  1899.6 1800.34 1900 1800.74 ;
    END
  END window_fault_o[5]
  PIN window_fault_o[6]
    DIRECTION OUTPUT ;
    USE SIGNAL ;
    PORT
      LAYER Metal3 ;
        RECT  1899.6 1802.86 1900 1803.26 ;
    END
  END window_fault_o[6]
  PIN window_fault_o[7]
    DIRECTION OUTPUT ;
    USE SIGNAL ;
    PORT
      LAYER Metal3 ;
        RECT  1899.6 1805.38 1900 1805.78 ;
    END
  END window_fault_o[7]
  PIN window_fault_o[8]
    DIRECTION OUTPUT ;
    USE SIGNAL ;
    PORT
      LAYER Metal3 ;
        RECT  1899.6 1807.9 1900 1808.3 ;
    END
  END window_fault_o[8]
  PIN window_fault_o[9]
    DIRECTION OUTPUT ;
    USE SIGNAL ;
    PORT
      LAYER Metal3 ;
        RECT  1899.6 1810.42 1900 1810.82 ;
    END
  END window_fault_o[9]
  PIN window_o[0]
    DIRECTION OUTPUT ;
    USE SIGNAL ;
    PORT
      LAYER Metal3 ;
        RECT  1899.6 1142.62 1900 1143.02 ;
    END
  END window_o[0]
  PIN window_o[100]
    DIRECTION OUTPUT ;
    USE SIGNAL ;
    PORT
      LAYER Metal3 ;
        RECT  1899.6 1394.62 1900 1395.02 ;
    END
  END window_o[100]
  PIN window_o[101]
    DIRECTION OUTPUT ;
    USE SIGNAL ;
    PORT
      LAYER Metal3 ;
        RECT  1899.6 1397.14 1900 1397.54 ;
    END
  END window_o[101]
  PIN window_o[102]
    DIRECTION OUTPUT ;
    USE SIGNAL ;
    PORT
      LAYER Metal3 ;
        RECT  1899.6 1399.66 1900 1400.06 ;
    END
  END window_o[102]
  PIN window_o[103]
    DIRECTION OUTPUT ;
    USE SIGNAL ;
    PORT
      LAYER Metal3 ;
        RECT  1899.6 1402.18 1900 1402.58 ;
    END
  END window_o[103]
  PIN window_o[104]
    DIRECTION OUTPUT ;
    USE SIGNAL ;
    PORT
      LAYER Metal3 ;
        RECT  1899.6 1404.7 1900 1405.1 ;
    END
  END window_o[104]
  PIN window_o[105]
    DIRECTION OUTPUT ;
    USE SIGNAL ;
    PORT
      LAYER Metal3 ;
        RECT  1899.6 1407.22 1900 1407.62 ;
    END
  END window_o[105]
  PIN window_o[106]
    DIRECTION OUTPUT ;
    USE SIGNAL ;
    PORT
      LAYER Metal3 ;
        RECT  1899.6 1409.74 1900 1410.14 ;
    END
  END window_o[106]
  PIN window_o[107]
    DIRECTION OUTPUT ;
    USE SIGNAL ;
    PORT
      LAYER Metal3 ;
        RECT  1899.6 1412.26 1900 1412.66 ;
    END
  END window_o[107]
  PIN window_o[108]
    DIRECTION OUTPUT ;
    USE SIGNAL ;
    PORT
      LAYER Metal3 ;
        RECT  1899.6 1414.78 1900 1415.18 ;
    END
  END window_o[108]
  PIN window_o[109]
    DIRECTION OUTPUT ;
    USE SIGNAL ;
    PORT
      LAYER Metal3 ;
        RECT  1899.6 1417.3 1900 1417.7 ;
    END
  END window_o[109]
  PIN window_o[10]
    DIRECTION OUTPUT ;
    USE SIGNAL ;
    PORT
      LAYER Metal3 ;
        RECT  1899.6 1167.82 1900 1168.22 ;
    END
  END window_o[10]
  PIN window_o[110]
    DIRECTION OUTPUT ;
    USE SIGNAL ;
    PORT
      LAYER Metal3 ;
        RECT  1899.6 1419.82 1900 1420.22 ;
    END
  END window_o[110]
  PIN window_o[111]
    DIRECTION OUTPUT ;
    USE SIGNAL ;
    PORT
      LAYER Metal3 ;
        RECT  1899.6 1422.34 1900 1422.74 ;
    END
  END window_o[111]
  PIN window_o[112]
    DIRECTION OUTPUT ;
    USE SIGNAL ;
    PORT
      LAYER Metal3 ;
        RECT  1899.6 1424.86 1900 1425.26 ;
    END
  END window_o[112]
  PIN window_o[113]
    DIRECTION OUTPUT ;
    USE SIGNAL ;
    PORT
      LAYER Metal3 ;
        RECT  1899.6 1427.38 1900 1427.78 ;
    END
  END window_o[113]
  PIN window_o[114]
    DIRECTION OUTPUT ;
    USE SIGNAL ;
    PORT
      LAYER Metal3 ;
        RECT  1899.6 1429.9 1900 1430.3 ;
    END
  END window_o[114]
  PIN window_o[115]
    DIRECTION OUTPUT ;
    USE SIGNAL ;
    PORT
      LAYER Metal3 ;
        RECT  1899.6 1432.42 1900 1432.82 ;
    END
  END window_o[115]
  PIN window_o[116]
    DIRECTION OUTPUT ;
    USE SIGNAL ;
    PORT
      LAYER Metal3 ;
        RECT  1899.6 1434.94 1900 1435.34 ;
    END
  END window_o[116]
  PIN window_o[117]
    DIRECTION OUTPUT ;
    USE SIGNAL ;
    PORT
      LAYER Metal3 ;
        RECT  1899.6 1437.46 1900 1437.86 ;
    END
  END window_o[117]
  PIN window_o[118]
    DIRECTION OUTPUT ;
    USE SIGNAL ;
    PORT
      LAYER Metal3 ;
        RECT  1899.6 1439.98 1900 1440.38 ;
    END
  END window_o[118]
  PIN window_o[119]
    DIRECTION OUTPUT ;
    USE SIGNAL ;
    PORT
      LAYER Metal3 ;
        RECT  1899.6 1442.5 1900 1442.9 ;
    END
  END window_o[119]
  PIN window_o[11]
    DIRECTION OUTPUT ;
    USE SIGNAL ;
    PORT
      LAYER Metal3 ;
        RECT  1899.6 1170.34 1900 1170.74 ;
    END
  END window_o[11]
  PIN window_o[120]
    DIRECTION OUTPUT ;
    USE SIGNAL ;
    PORT
      LAYER Metal3 ;
        RECT  1899.6 1445.02 1900 1445.42 ;
    END
  END window_o[120]
  PIN window_o[121]
    DIRECTION OUTPUT ;
    USE SIGNAL ;
    PORT
      LAYER Metal3 ;
        RECT  1899.6 1447.54 1900 1447.94 ;
    END
  END window_o[121]
  PIN window_o[122]
    DIRECTION OUTPUT ;
    USE SIGNAL ;
    PORT
      LAYER Metal3 ;
        RECT  1899.6 1450.06 1900 1450.46 ;
    END
  END window_o[122]
  PIN window_o[123]
    DIRECTION OUTPUT ;
    USE SIGNAL ;
    PORT
      LAYER Metal3 ;
        RECT  1899.6 1452.58 1900 1452.98 ;
    END
  END window_o[123]
  PIN window_o[124]
    DIRECTION OUTPUT ;
    USE SIGNAL ;
    PORT
      LAYER Metal3 ;
        RECT  1899.6 1455.1 1900 1455.5 ;
    END
  END window_o[124]
  PIN window_o[125]
    DIRECTION OUTPUT ;
    USE SIGNAL ;
    PORT
      LAYER Metal3 ;
        RECT  1899.6 1457.62 1900 1458.02 ;
    END
  END window_o[125]
  PIN window_o[126]
    DIRECTION OUTPUT ;
    USE SIGNAL ;
    PORT
      LAYER Metal3 ;
        RECT  1899.6 1460.14 1900 1460.54 ;
    END
  END window_o[126]
  PIN window_o[127]
    DIRECTION OUTPUT ;
    USE SIGNAL ;
    PORT
      LAYER Metal3 ;
        RECT  1899.6 1462.66 1900 1463.06 ;
    END
  END window_o[127]
  PIN window_o[128]
    DIRECTION OUTPUT ;
    USE SIGNAL ;
    PORT
      LAYER Metal3 ;
        RECT  1899.6 1465.18 1900 1465.58 ;
    END
  END window_o[128]
  PIN window_o[129]
    DIRECTION OUTPUT ;
    USE SIGNAL ;
    PORT
      LAYER Metal3 ;
        RECT  1899.6 1467.7 1900 1468.1 ;
    END
  END window_o[129]
  PIN window_o[12]
    DIRECTION OUTPUT ;
    USE SIGNAL ;
    PORT
      LAYER Metal3 ;
        RECT  1899.6 1172.86 1900 1173.26 ;
    END
  END window_o[12]
  PIN window_o[130]
    DIRECTION OUTPUT ;
    USE SIGNAL ;
    PORT
      LAYER Metal3 ;
        RECT  1899.6 1470.22 1900 1470.62 ;
    END
  END window_o[130]
  PIN window_o[131]
    DIRECTION OUTPUT ;
    USE SIGNAL ;
    PORT
      LAYER Metal3 ;
        RECT  1899.6 1472.74 1900 1473.14 ;
    END
  END window_o[131]
  PIN window_o[132]
    DIRECTION OUTPUT ;
    USE SIGNAL ;
    PORT
      LAYER Metal3 ;
        RECT  1899.6 1475.26 1900 1475.66 ;
    END
  END window_o[132]
  PIN window_o[133]
    DIRECTION OUTPUT ;
    USE SIGNAL ;
    PORT
      LAYER Metal3 ;
        RECT  1899.6 1477.78 1900 1478.18 ;
    END
  END window_o[133]
  PIN window_o[134]
    DIRECTION OUTPUT ;
    USE SIGNAL ;
    PORT
      LAYER Metal3 ;
        RECT  1899.6 1480.3 1900 1480.7 ;
    END
  END window_o[134]
  PIN window_o[135]
    DIRECTION OUTPUT ;
    USE SIGNAL ;
    PORT
      LAYER Metal3 ;
        RECT  1899.6 1482.82 1900 1483.22 ;
    END
  END window_o[135]
  PIN window_o[136]
    DIRECTION OUTPUT ;
    USE SIGNAL ;
    PORT
      LAYER Metal3 ;
        RECT  1899.6 1485.34 1900 1485.74 ;
    END
  END window_o[136]
  PIN window_o[137]
    DIRECTION OUTPUT ;
    USE SIGNAL ;
    PORT
      LAYER Metal3 ;
        RECT  1899.6 1487.86 1900 1488.26 ;
    END
  END window_o[137]
  PIN window_o[138]
    DIRECTION OUTPUT ;
    USE SIGNAL ;
    PORT
      LAYER Metal3 ;
        RECT  1899.6 1490.38 1900 1490.78 ;
    END
  END window_o[138]
  PIN window_o[139]
    DIRECTION OUTPUT ;
    USE SIGNAL ;
    PORT
      LAYER Metal3 ;
        RECT  1899.6 1492.9 1900 1493.3 ;
    END
  END window_o[139]
  PIN window_o[13]
    DIRECTION OUTPUT ;
    USE SIGNAL ;
    PORT
      LAYER Metal3 ;
        RECT  1899.6 1175.38 1900 1175.78 ;
    END
  END window_o[13]
  PIN window_o[140]
    DIRECTION OUTPUT ;
    USE SIGNAL ;
    PORT
      LAYER Metal3 ;
        RECT  1899.6 1495.42 1900 1495.82 ;
    END
  END window_o[140]
  PIN window_o[141]
    DIRECTION OUTPUT ;
    USE SIGNAL ;
    PORT
      LAYER Metal3 ;
        RECT  1899.6 1497.94 1900 1498.34 ;
    END
  END window_o[141]
  PIN window_o[142]
    DIRECTION OUTPUT ;
    USE SIGNAL ;
    PORT
      LAYER Metal3 ;
        RECT  1899.6 1500.46 1900 1500.86 ;
    END
  END window_o[142]
  PIN window_o[143]
    DIRECTION OUTPUT ;
    USE SIGNAL ;
    PORT
      LAYER Metal3 ;
        RECT  1899.6 1502.98 1900 1503.38 ;
    END
  END window_o[143]
  PIN window_o[144]
    DIRECTION OUTPUT ;
    USE SIGNAL ;
    PORT
      LAYER Metal3 ;
        RECT  1899.6 1505.5 1900 1505.9 ;
    END
  END window_o[144]
  PIN window_o[145]
    DIRECTION OUTPUT ;
    USE SIGNAL ;
    PORT
      LAYER Metal3 ;
        RECT  1899.6 1508.02 1900 1508.42 ;
    END
  END window_o[145]
  PIN window_o[146]
    DIRECTION OUTPUT ;
    USE SIGNAL ;
    PORT
      LAYER Metal3 ;
        RECT  1899.6 1510.54 1900 1510.94 ;
    END
  END window_o[146]
  PIN window_o[147]
    DIRECTION OUTPUT ;
    USE SIGNAL ;
    PORT
      LAYER Metal3 ;
        RECT  1899.6 1513.06 1900 1513.46 ;
    END
  END window_o[147]
  PIN window_o[148]
    DIRECTION OUTPUT ;
    USE SIGNAL ;
    PORT
      LAYER Metal3 ;
        RECT  1899.6 1515.58 1900 1515.98 ;
    END
  END window_o[148]
  PIN window_o[149]
    DIRECTION OUTPUT ;
    USE SIGNAL ;
    PORT
      LAYER Metal3 ;
        RECT  1899.6 1518.1 1900 1518.5 ;
    END
  END window_o[149]
  PIN window_o[14]
    DIRECTION OUTPUT ;
    USE SIGNAL ;
    PORT
      LAYER Metal3 ;
        RECT  1899.6 1177.9 1900 1178.3 ;
    END
  END window_o[14]
  PIN window_o[150]
    DIRECTION OUTPUT ;
    USE SIGNAL ;
    PORT
      LAYER Metal3 ;
        RECT  1899.6 1520.62 1900 1521.02 ;
    END
  END window_o[150]
  PIN window_o[151]
    DIRECTION OUTPUT ;
    USE SIGNAL ;
    PORT
      LAYER Metal3 ;
        RECT  1899.6 1523.14 1900 1523.54 ;
    END
  END window_o[151]
  PIN window_o[152]
    DIRECTION OUTPUT ;
    USE SIGNAL ;
    PORT
      LAYER Metal3 ;
        RECT  1899.6 1525.66 1900 1526.06 ;
    END
  END window_o[152]
  PIN window_o[153]
    DIRECTION OUTPUT ;
    USE SIGNAL ;
    PORT
      LAYER Metal3 ;
        RECT  1899.6 1528.18 1900 1528.58 ;
    END
  END window_o[153]
  PIN window_o[154]
    DIRECTION OUTPUT ;
    USE SIGNAL ;
    PORT
      LAYER Metal3 ;
        RECT  1899.6 1530.7 1900 1531.1 ;
    END
  END window_o[154]
  PIN window_o[155]
    DIRECTION OUTPUT ;
    USE SIGNAL ;
    PORT
      LAYER Metal3 ;
        RECT  1899.6 1533.22 1900 1533.62 ;
    END
  END window_o[155]
  PIN window_o[156]
    DIRECTION OUTPUT ;
    USE SIGNAL ;
    PORT
      LAYER Metal3 ;
        RECT  1899.6 1535.74 1900 1536.14 ;
    END
  END window_o[156]
  PIN window_o[157]
    DIRECTION OUTPUT ;
    USE SIGNAL ;
    PORT
      LAYER Metal3 ;
        RECT  1899.6 1538.26 1900 1538.66 ;
    END
  END window_o[157]
  PIN window_o[158]
    DIRECTION OUTPUT ;
    USE SIGNAL ;
    PORT
      LAYER Metal3 ;
        RECT  1899.6 1540.78 1900 1541.18 ;
    END
  END window_o[158]
  PIN window_o[159]
    DIRECTION OUTPUT ;
    USE SIGNAL ;
    PORT
      LAYER Metal3 ;
        RECT  1899.6 1543.3 1900 1543.7 ;
    END
  END window_o[159]
  PIN window_o[15]
    DIRECTION OUTPUT ;
    USE SIGNAL ;
    PORT
      LAYER Metal3 ;
        RECT  1899.6 1180.42 1900 1180.82 ;
    END
  END window_o[15]
  PIN window_o[160]
    DIRECTION OUTPUT ;
    USE SIGNAL ;
    PORT
      LAYER Metal3 ;
        RECT  1899.6 1545.82 1900 1546.22 ;
    END
  END window_o[160]
  PIN window_o[161]
    DIRECTION OUTPUT ;
    USE SIGNAL ;
    PORT
      LAYER Metal3 ;
        RECT  1899.6 1548.34 1900 1548.74 ;
    END
  END window_o[161]
  PIN window_o[162]
    DIRECTION OUTPUT ;
    USE SIGNAL ;
    PORT
      LAYER Metal3 ;
        RECT  1899.6 1550.86 1900 1551.26 ;
    END
  END window_o[162]
  PIN window_o[163]
    DIRECTION OUTPUT ;
    USE SIGNAL ;
    PORT
      LAYER Metal3 ;
        RECT  1899.6 1553.38 1900 1553.78 ;
    END
  END window_o[163]
  PIN window_o[164]
    DIRECTION OUTPUT ;
    USE SIGNAL ;
    PORT
      LAYER Metal3 ;
        RECT  1899.6 1555.9 1900 1556.3 ;
    END
  END window_o[164]
  PIN window_o[165]
    DIRECTION OUTPUT ;
    USE SIGNAL ;
    PORT
      LAYER Metal3 ;
        RECT  1899.6 1558.42 1900 1558.82 ;
    END
  END window_o[165]
  PIN window_o[166]
    DIRECTION OUTPUT ;
    USE SIGNAL ;
    PORT
      LAYER Metal3 ;
        RECT  1899.6 1560.94 1900 1561.34 ;
    END
  END window_o[166]
  PIN window_o[167]
    DIRECTION OUTPUT ;
    USE SIGNAL ;
    PORT
      LAYER Metal3 ;
        RECT  1899.6 1563.46 1900 1563.86 ;
    END
  END window_o[167]
  PIN window_o[168]
    DIRECTION OUTPUT ;
    USE SIGNAL ;
    PORT
      LAYER Metal3 ;
        RECT  1899.6 1565.98 1900 1566.38 ;
    END
  END window_o[168]
  PIN window_o[169]
    DIRECTION OUTPUT ;
    USE SIGNAL ;
    PORT
      LAYER Metal3 ;
        RECT  1899.6 1568.5 1900 1568.9 ;
    END
  END window_o[169]
  PIN window_o[16]
    DIRECTION OUTPUT ;
    USE SIGNAL ;
    PORT
      LAYER Metal3 ;
        RECT  1899.6 1182.94 1900 1183.34 ;
    END
  END window_o[16]
  PIN window_o[170]
    DIRECTION OUTPUT ;
    USE SIGNAL ;
    PORT
      LAYER Metal3 ;
        RECT  1899.6 1571.02 1900 1571.42 ;
    END
  END window_o[170]
  PIN window_o[171]
    DIRECTION OUTPUT ;
    USE SIGNAL ;
    PORT
      LAYER Metal3 ;
        RECT  1899.6 1573.54 1900 1573.94 ;
    END
  END window_o[171]
  PIN window_o[172]
    DIRECTION OUTPUT ;
    USE SIGNAL ;
    PORT
      LAYER Metal3 ;
        RECT  1899.6 1576.06 1900 1576.46 ;
    END
  END window_o[172]
  PIN window_o[173]
    DIRECTION OUTPUT ;
    USE SIGNAL ;
    PORT
      LAYER Metal3 ;
        RECT  1899.6 1578.58 1900 1578.98 ;
    END
  END window_o[173]
  PIN window_o[174]
    DIRECTION OUTPUT ;
    USE SIGNAL ;
    PORT
      LAYER Metal3 ;
        RECT  1899.6 1581.1 1900 1581.5 ;
    END
  END window_o[174]
  PIN window_o[175]
    DIRECTION OUTPUT ;
    USE SIGNAL ;
    PORT
      LAYER Metal3 ;
        RECT  1899.6 1583.62 1900 1584.02 ;
    END
  END window_o[175]
  PIN window_o[176]
    DIRECTION OUTPUT ;
    USE SIGNAL ;
    PORT
      LAYER Metal3 ;
        RECT  1899.6 1586.14 1900 1586.54 ;
    END
  END window_o[176]
  PIN window_o[177]
    DIRECTION OUTPUT ;
    USE SIGNAL ;
    PORT
      LAYER Metal3 ;
        RECT  1899.6 1588.66 1900 1589.06 ;
    END
  END window_o[177]
  PIN window_o[178]
    DIRECTION OUTPUT ;
    USE SIGNAL ;
    PORT
      LAYER Metal3 ;
        RECT  1899.6 1591.18 1900 1591.58 ;
    END
  END window_o[178]
  PIN window_o[179]
    DIRECTION OUTPUT ;
    USE SIGNAL ;
    PORT
      LAYER Metal3 ;
        RECT  1899.6 1593.7 1900 1594.1 ;
    END
  END window_o[179]
  PIN window_o[17]
    DIRECTION OUTPUT ;
    USE SIGNAL ;
    PORT
      LAYER Metal3 ;
        RECT  1899.6 1185.46 1900 1185.86 ;
    END
  END window_o[17]
  PIN window_o[180]
    DIRECTION OUTPUT ;
    USE SIGNAL ;
    PORT
      LAYER Metal3 ;
        RECT  1899.6 1596.22 1900 1596.62 ;
    END
  END window_o[180]
  PIN window_o[181]
    DIRECTION OUTPUT ;
    USE SIGNAL ;
    PORT
      LAYER Metal3 ;
        RECT  1899.6 1598.74 1900 1599.14 ;
    END
  END window_o[181]
  PIN window_o[182]
    DIRECTION OUTPUT ;
    USE SIGNAL ;
    PORT
      LAYER Metal3 ;
        RECT  1899.6 1601.26 1900 1601.66 ;
    END
  END window_o[182]
  PIN window_o[183]
    DIRECTION OUTPUT ;
    USE SIGNAL ;
    PORT
      LAYER Metal3 ;
        RECT  1899.6 1603.78 1900 1604.18 ;
    END
  END window_o[183]
  PIN window_o[184]
    DIRECTION OUTPUT ;
    USE SIGNAL ;
    PORT
      LAYER Metal3 ;
        RECT  1899.6 1606.3 1900 1606.7 ;
    END
  END window_o[184]
  PIN window_o[185]
    DIRECTION OUTPUT ;
    USE SIGNAL ;
    PORT
      LAYER Metal3 ;
        RECT  1899.6 1608.82 1900 1609.22 ;
    END
  END window_o[185]
  PIN window_o[186]
    DIRECTION OUTPUT ;
    USE SIGNAL ;
    PORT
      LAYER Metal3 ;
        RECT  1899.6 1611.34 1900 1611.74 ;
    END
  END window_o[186]
  PIN window_o[187]
    DIRECTION OUTPUT ;
    USE SIGNAL ;
    PORT
      LAYER Metal3 ;
        RECT  1899.6 1613.86 1900 1614.26 ;
    END
  END window_o[187]
  PIN window_o[188]
    DIRECTION OUTPUT ;
    USE SIGNAL ;
    PORT
      LAYER Metal3 ;
        RECT  1899.6 1616.38 1900 1616.78 ;
    END
  END window_o[188]
  PIN window_o[189]
    DIRECTION OUTPUT ;
    USE SIGNAL ;
    PORT
      LAYER Metal3 ;
        RECT  1899.6 1618.9 1900 1619.3 ;
    END
  END window_o[189]
  PIN window_o[18]
    DIRECTION OUTPUT ;
    USE SIGNAL ;
    PORT
      LAYER Metal3 ;
        RECT  1899.6 1187.98 1900 1188.38 ;
    END
  END window_o[18]
  PIN window_o[190]
    DIRECTION OUTPUT ;
    USE SIGNAL ;
    PORT
      LAYER Metal3 ;
        RECT  1899.6 1621.42 1900 1621.82 ;
    END
  END window_o[190]
  PIN window_o[191]
    DIRECTION OUTPUT ;
    USE SIGNAL ;
    PORT
      LAYER Metal3 ;
        RECT  1899.6 1623.94 1900 1624.34 ;
    END
  END window_o[191]
  PIN window_o[192]
    DIRECTION OUTPUT ;
    USE SIGNAL ;
    PORT
      LAYER Metal3 ;
        RECT  1899.6 1626.46 1900 1626.86 ;
    END
  END window_o[192]
  PIN window_o[193]
    DIRECTION OUTPUT ;
    USE SIGNAL ;
    PORT
      LAYER Metal3 ;
        RECT  1899.6 1628.98 1900 1629.38 ;
    END
  END window_o[193]
  PIN window_o[194]
    DIRECTION OUTPUT ;
    USE SIGNAL ;
    PORT
      LAYER Metal3 ;
        RECT  1899.6 1631.5 1900 1631.9 ;
    END
  END window_o[194]
  PIN window_o[195]
    DIRECTION OUTPUT ;
    USE SIGNAL ;
    PORT
      LAYER Metal3 ;
        RECT  1899.6 1634.02 1900 1634.42 ;
    END
  END window_o[195]
  PIN window_o[196]
    DIRECTION OUTPUT ;
    USE SIGNAL ;
    PORT
      LAYER Metal3 ;
        RECT  1899.6 1636.54 1900 1636.94 ;
    END
  END window_o[196]
  PIN window_o[197]
    DIRECTION OUTPUT ;
    USE SIGNAL ;
    PORT
      LAYER Metal3 ;
        RECT  1899.6 1639.06 1900 1639.46 ;
    END
  END window_o[197]
  PIN window_o[198]
    DIRECTION OUTPUT ;
    USE SIGNAL ;
    PORT
      LAYER Metal3 ;
        RECT  1899.6 1641.58 1900 1641.98 ;
    END
  END window_o[198]
  PIN window_o[199]
    DIRECTION OUTPUT ;
    USE SIGNAL ;
    PORT
      LAYER Metal3 ;
        RECT  1899.6 1644.1 1900 1644.5 ;
    END
  END window_o[199]
  PIN window_o[19]
    DIRECTION OUTPUT ;
    USE SIGNAL ;
    PORT
      LAYER Metal3 ;
        RECT  1899.6 1190.5 1900 1190.9 ;
    END
  END window_o[19]
  PIN window_o[1]
    DIRECTION OUTPUT ;
    USE SIGNAL ;
    PORT
      LAYER Metal3 ;
        RECT  1899.6 1145.14 1900 1145.54 ;
    END
  END window_o[1]
  PIN window_o[200]
    DIRECTION OUTPUT ;
    USE SIGNAL ;
    PORT
      LAYER Metal3 ;
        RECT  1899.6 1646.62 1900 1647.02 ;
    END
  END window_o[200]
  PIN window_o[201]
    DIRECTION OUTPUT ;
    USE SIGNAL ;
    PORT
      LAYER Metal3 ;
        RECT  1899.6 1649.14 1900 1649.54 ;
    END
  END window_o[201]
  PIN window_o[202]
    DIRECTION OUTPUT ;
    USE SIGNAL ;
    PORT
      LAYER Metal3 ;
        RECT  1899.6 1651.66 1900 1652.06 ;
    END
  END window_o[202]
  PIN window_o[203]
    DIRECTION OUTPUT ;
    USE SIGNAL ;
    PORT
      LAYER Metal3 ;
        RECT  1899.6 1654.18 1900 1654.58 ;
    END
  END window_o[203]
  PIN window_o[204]
    DIRECTION OUTPUT ;
    USE SIGNAL ;
    PORT
      LAYER Metal3 ;
        RECT  1899.6 1656.7 1900 1657.1 ;
    END
  END window_o[204]
  PIN window_o[205]
    DIRECTION OUTPUT ;
    USE SIGNAL ;
    PORT
      LAYER Metal3 ;
        RECT  1899.6 1659.22 1900 1659.62 ;
    END
  END window_o[205]
  PIN window_o[206]
    DIRECTION OUTPUT ;
    USE SIGNAL ;
    PORT
      LAYER Metal3 ;
        RECT  1899.6 1661.74 1900 1662.14 ;
    END
  END window_o[206]
  PIN window_o[207]
    DIRECTION OUTPUT ;
    USE SIGNAL ;
    PORT
      LAYER Metal3 ;
        RECT  1899.6 1664.26 1900 1664.66 ;
    END
  END window_o[207]
  PIN window_o[208]
    DIRECTION OUTPUT ;
    USE SIGNAL ;
    PORT
      LAYER Metal3 ;
        RECT  1899.6 1666.78 1900 1667.18 ;
    END
  END window_o[208]
  PIN window_o[209]
    DIRECTION OUTPUT ;
    USE SIGNAL ;
    PORT
      LAYER Metal3 ;
        RECT  1899.6 1669.3 1900 1669.7 ;
    END
  END window_o[209]
  PIN window_o[20]
    DIRECTION OUTPUT ;
    USE SIGNAL ;
    PORT
      LAYER Metal3 ;
        RECT  1899.6 1193.02 1900 1193.42 ;
    END
  END window_o[20]
  PIN window_o[210]
    DIRECTION OUTPUT ;
    USE SIGNAL ;
    PORT
      LAYER Metal3 ;
        RECT  1899.6 1671.82 1900 1672.22 ;
    END
  END window_o[210]
  PIN window_o[211]
    DIRECTION OUTPUT ;
    USE SIGNAL ;
    PORT
      LAYER Metal3 ;
        RECT  1899.6 1674.34 1900 1674.74 ;
    END
  END window_o[211]
  PIN window_o[212]
    DIRECTION OUTPUT ;
    USE SIGNAL ;
    PORT
      LAYER Metal3 ;
        RECT  1899.6 1676.86 1900 1677.26 ;
    END
  END window_o[212]
  PIN window_o[213]
    DIRECTION OUTPUT ;
    USE SIGNAL ;
    PORT
      LAYER Metal3 ;
        RECT  1899.6 1679.38 1900 1679.78 ;
    END
  END window_o[213]
  PIN window_o[214]
    DIRECTION OUTPUT ;
    USE SIGNAL ;
    PORT
      LAYER Metal3 ;
        RECT  1899.6 1681.9 1900 1682.3 ;
    END
  END window_o[214]
  PIN window_o[215]
    DIRECTION OUTPUT ;
    USE SIGNAL ;
    PORT
      LAYER Metal3 ;
        RECT  1899.6 1684.42 1900 1684.82 ;
    END
  END window_o[215]
  PIN window_o[216]
    DIRECTION OUTPUT ;
    USE SIGNAL ;
    PORT
      LAYER Metal3 ;
        RECT  1899.6 1686.94 1900 1687.34 ;
    END
  END window_o[216]
  PIN window_o[217]
    DIRECTION OUTPUT ;
    USE SIGNAL ;
    PORT
      LAYER Metal3 ;
        RECT  1899.6 1689.46 1900 1689.86 ;
    END
  END window_o[217]
  PIN window_o[218]
    DIRECTION OUTPUT ;
    USE SIGNAL ;
    PORT
      LAYER Metal3 ;
        RECT  1899.6 1691.98 1900 1692.38 ;
    END
  END window_o[218]
  PIN window_o[219]
    DIRECTION OUTPUT ;
    USE SIGNAL ;
    PORT
      LAYER Metal3 ;
        RECT  1899.6 1694.5 1900 1694.9 ;
    END
  END window_o[219]
  PIN window_o[21]
    DIRECTION OUTPUT ;
    USE SIGNAL ;
    PORT
      LAYER Metal3 ;
        RECT  1899.6 1195.54 1900 1195.94 ;
    END
  END window_o[21]
  PIN window_o[220]
    DIRECTION OUTPUT ;
    USE SIGNAL ;
    PORT
      LAYER Metal3 ;
        RECT  1899.6 1697.02 1900 1697.42 ;
    END
  END window_o[220]
  PIN window_o[221]
    DIRECTION OUTPUT ;
    USE SIGNAL ;
    PORT
      LAYER Metal3 ;
        RECT  1899.6 1699.54 1900 1699.94 ;
    END
  END window_o[221]
  PIN window_o[222]
    DIRECTION OUTPUT ;
    USE SIGNAL ;
    PORT
      LAYER Metal3 ;
        RECT  1899.6 1702.06 1900 1702.46 ;
    END
  END window_o[222]
  PIN window_o[223]
    DIRECTION OUTPUT ;
    USE SIGNAL ;
    PORT
      LAYER Metal3 ;
        RECT  1899.6 1704.58 1900 1704.98 ;
    END
  END window_o[223]
  PIN window_o[224]
    DIRECTION OUTPUT ;
    USE SIGNAL ;
    PORT
      LAYER Metal3 ;
        RECT  1899.6 1707.1 1900 1707.5 ;
    END
  END window_o[224]
  PIN window_o[225]
    DIRECTION OUTPUT ;
    USE SIGNAL ;
    PORT
      LAYER Metal3 ;
        RECT  1899.6 1709.62 1900 1710.02 ;
    END
  END window_o[225]
  PIN window_o[226]
    DIRECTION OUTPUT ;
    USE SIGNAL ;
    PORT
      LAYER Metal3 ;
        RECT  1899.6 1712.14 1900 1712.54 ;
    END
  END window_o[226]
  PIN window_o[227]
    DIRECTION OUTPUT ;
    USE SIGNAL ;
    PORT
      LAYER Metal3 ;
        RECT  1899.6 1714.66 1900 1715.06 ;
    END
  END window_o[227]
  PIN window_o[228]
    DIRECTION OUTPUT ;
    USE SIGNAL ;
    PORT
      LAYER Metal3 ;
        RECT  1899.6 1717.18 1900 1717.58 ;
    END
  END window_o[228]
  PIN window_o[229]
    DIRECTION OUTPUT ;
    USE SIGNAL ;
    PORT
      LAYER Metal3 ;
        RECT  1899.6 1719.7 1900 1720.1 ;
    END
  END window_o[229]
  PIN window_o[22]
    DIRECTION OUTPUT ;
    USE SIGNAL ;
    PORT
      LAYER Metal3 ;
        RECT  1899.6 1198.06 1900 1198.46 ;
    END
  END window_o[22]
  PIN window_o[230]
    DIRECTION OUTPUT ;
    USE SIGNAL ;
    PORT
      LAYER Metal3 ;
        RECT  1899.6 1722.22 1900 1722.62 ;
    END
  END window_o[230]
  PIN window_o[231]
    DIRECTION OUTPUT ;
    USE SIGNAL ;
    PORT
      LAYER Metal3 ;
        RECT  1899.6 1724.74 1900 1725.14 ;
    END
  END window_o[231]
  PIN window_o[232]
    DIRECTION OUTPUT ;
    USE SIGNAL ;
    PORT
      LAYER Metal3 ;
        RECT  1899.6 1727.26 1900 1727.66 ;
    END
  END window_o[232]
  PIN window_o[233]
    DIRECTION OUTPUT ;
    USE SIGNAL ;
    PORT
      LAYER Metal3 ;
        RECT  1899.6 1729.78 1900 1730.18 ;
    END
  END window_o[233]
  PIN window_o[234]
    DIRECTION OUTPUT ;
    USE SIGNAL ;
    PORT
      LAYER Metal3 ;
        RECT  1899.6 1732.3 1900 1732.7 ;
    END
  END window_o[234]
  PIN window_o[235]
    DIRECTION OUTPUT ;
    USE SIGNAL ;
    PORT
      LAYER Metal3 ;
        RECT  1899.6 1734.82 1900 1735.22 ;
    END
  END window_o[235]
  PIN window_o[236]
    DIRECTION OUTPUT ;
    USE SIGNAL ;
    PORT
      LAYER Metal3 ;
        RECT  1899.6 1737.34 1900 1737.74 ;
    END
  END window_o[236]
  PIN window_o[237]
    DIRECTION OUTPUT ;
    USE SIGNAL ;
    PORT
      LAYER Metal3 ;
        RECT  1899.6 1739.86 1900 1740.26 ;
    END
  END window_o[237]
  PIN window_o[238]
    DIRECTION OUTPUT ;
    USE SIGNAL ;
    PORT
      LAYER Metal3 ;
        RECT  1899.6 1742.38 1900 1742.78 ;
    END
  END window_o[238]
  PIN window_o[239]
    DIRECTION OUTPUT ;
    USE SIGNAL ;
    PORT
      LAYER Metal3 ;
        RECT  1899.6 1744.9 1900 1745.3 ;
    END
  END window_o[239]
  PIN window_o[23]
    DIRECTION OUTPUT ;
    USE SIGNAL ;
    PORT
      LAYER Metal3 ;
        RECT  1899.6 1200.58 1900 1200.98 ;
    END
  END window_o[23]
  PIN window_o[240]
    DIRECTION OUTPUT ;
    USE SIGNAL ;
    PORT
      LAYER Metal3 ;
        RECT  1899.6 1747.42 1900 1747.82 ;
    END
  END window_o[240]
  PIN window_o[241]
    DIRECTION OUTPUT ;
    USE SIGNAL ;
    PORT
      LAYER Metal3 ;
        RECT  1899.6 1749.94 1900 1750.34 ;
    END
  END window_o[241]
  PIN window_o[242]
    DIRECTION OUTPUT ;
    USE SIGNAL ;
    PORT
      LAYER Metal3 ;
        RECT  1899.6 1752.46 1900 1752.86 ;
    END
  END window_o[242]
  PIN window_o[243]
    DIRECTION OUTPUT ;
    USE SIGNAL ;
    PORT
      LAYER Metal3 ;
        RECT  1899.6 1754.98 1900 1755.38 ;
    END
  END window_o[243]
  PIN window_o[244]
    DIRECTION OUTPUT ;
    USE SIGNAL ;
    PORT
      LAYER Metal3 ;
        RECT  1899.6 1757.5 1900 1757.9 ;
    END
  END window_o[244]
  PIN window_o[245]
    DIRECTION OUTPUT ;
    USE SIGNAL ;
    PORT
      LAYER Metal3 ;
        RECT  1899.6 1760.02 1900 1760.42 ;
    END
  END window_o[245]
  PIN window_o[246]
    DIRECTION OUTPUT ;
    USE SIGNAL ;
    PORT
      LAYER Metal3 ;
        RECT  1899.6 1762.54 1900 1762.94 ;
    END
  END window_o[246]
  PIN window_o[247]
    DIRECTION OUTPUT ;
    USE SIGNAL ;
    PORT
      LAYER Metal3 ;
        RECT  1899.6 1765.06 1900 1765.46 ;
    END
  END window_o[247]
  PIN window_o[248]
    DIRECTION OUTPUT ;
    USE SIGNAL ;
    PORT
      LAYER Metal3 ;
        RECT  1899.6 1767.58 1900 1767.98 ;
    END
  END window_o[248]
  PIN window_o[249]
    DIRECTION OUTPUT ;
    USE SIGNAL ;
    PORT
      LAYER Metal3 ;
        RECT  1899.6 1770.1 1900 1770.5 ;
    END
  END window_o[249]
  PIN window_o[24]
    DIRECTION OUTPUT ;
    USE SIGNAL ;
    PORT
      LAYER Metal3 ;
        RECT  1899.6 1203.1 1900 1203.5 ;
    END
  END window_o[24]
  PIN window_o[250]
    DIRECTION OUTPUT ;
    USE SIGNAL ;
    PORT
      LAYER Metal3 ;
        RECT  1899.6 1772.62 1900 1773.02 ;
    END
  END window_o[250]
  PIN window_o[251]
    DIRECTION OUTPUT ;
    USE SIGNAL ;
    PORT
      LAYER Metal3 ;
        RECT  1899.6 1775.14 1900 1775.54 ;
    END
  END window_o[251]
  PIN window_o[252]
    DIRECTION OUTPUT ;
    USE SIGNAL ;
    PORT
      LAYER Metal3 ;
        RECT  1899.6 1777.66 1900 1778.06 ;
    END
  END window_o[252]
  PIN window_o[253]
    DIRECTION OUTPUT ;
    USE SIGNAL ;
    PORT
      LAYER Metal3 ;
        RECT  1899.6 1780.18 1900 1780.58 ;
    END
  END window_o[253]
  PIN window_o[254]
    DIRECTION OUTPUT ;
    USE SIGNAL ;
    PORT
      LAYER Metal3 ;
        RECT  1899.6 1782.7 1900 1783.1 ;
    END
  END window_o[254]
  PIN window_o[255]
    DIRECTION OUTPUT ;
    USE SIGNAL ;
    PORT
      LAYER Metal3 ;
        RECT  1899.6 1785.22 1900 1785.62 ;
    END
  END window_o[255]
  PIN window_o[25]
    DIRECTION OUTPUT ;
    USE SIGNAL ;
    PORT
      LAYER Metal3 ;
        RECT  1899.6 1205.62 1900 1206.02 ;
    END
  END window_o[25]
  PIN window_o[26]
    DIRECTION OUTPUT ;
    USE SIGNAL ;
    PORT
      LAYER Metal3 ;
        RECT  1899.6 1208.14 1900 1208.54 ;
    END
  END window_o[26]
  PIN window_o[27]
    DIRECTION OUTPUT ;
    USE SIGNAL ;
    PORT
      LAYER Metal3 ;
        RECT  1899.6 1210.66 1900 1211.06 ;
    END
  END window_o[27]
  PIN window_o[28]
    DIRECTION OUTPUT ;
    USE SIGNAL ;
    PORT
      LAYER Metal3 ;
        RECT  1899.6 1213.18 1900 1213.58 ;
    END
  END window_o[28]
  PIN window_o[29]
    DIRECTION OUTPUT ;
    USE SIGNAL ;
    PORT
      LAYER Metal3 ;
        RECT  1899.6 1215.7 1900 1216.1 ;
    END
  END window_o[29]
  PIN window_o[2]
    DIRECTION OUTPUT ;
    USE SIGNAL ;
    PORT
      LAYER Metal3 ;
        RECT  1899.6 1147.66 1900 1148.06 ;
    END
  END window_o[2]
  PIN window_o[30]
    DIRECTION OUTPUT ;
    USE SIGNAL ;
    PORT
      LAYER Metal3 ;
        RECT  1899.6 1218.22 1900 1218.62 ;
    END
  END window_o[30]
  PIN window_o[31]
    DIRECTION OUTPUT ;
    USE SIGNAL ;
    PORT
      LAYER Metal3 ;
        RECT  1899.6 1220.74 1900 1221.14 ;
    END
  END window_o[31]
  PIN window_o[32]
    DIRECTION OUTPUT ;
    USE SIGNAL ;
    PORT
      LAYER Metal3 ;
        RECT  1899.6 1223.26 1900 1223.66 ;
    END
  END window_o[32]
  PIN window_o[33]
    DIRECTION OUTPUT ;
    USE SIGNAL ;
    PORT
      LAYER Metal3 ;
        RECT  1899.6 1225.78 1900 1226.18 ;
    END
  END window_o[33]
  PIN window_o[34]
    DIRECTION OUTPUT ;
    USE SIGNAL ;
    PORT
      LAYER Metal3 ;
        RECT  1899.6 1228.3 1900 1228.7 ;
    END
  END window_o[34]
  PIN window_o[35]
    DIRECTION OUTPUT ;
    USE SIGNAL ;
    PORT
      LAYER Metal3 ;
        RECT  1899.6 1230.82 1900 1231.22 ;
    END
  END window_o[35]
  PIN window_o[36]
    DIRECTION OUTPUT ;
    USE SIGNAL ;
    PORT
      LAYER Metal3 ;
        RECT  1899.6 1233.34 1900 1233.74 ;
    END
  END window_o[36]
  PIN window_o[37]
    DIRECTION OUTPUT ;
    USE SIGNAL ;
    PORT
      LAYER Metal3 ;
        RECT  1899.6 1235.86 1900 1236.26 ;
    END
  END window_o[37]
  PIN window_o[38]
    DIRECTION OUTPUT ;
    USE SIGNAL ;
    PORT
      LAYER Metal3 ;
        RECT  1899.6 1238.38 1900 1238.78 ;
    END
  END window_o[38]
  PIN window_o[39]
    DIRECTION OUTPUT ;
    USE SIGNAL ;
    PORT
      LAYER Metal3 ;
        RECT  1899.6 1240.9 1900 1241.3 ;
    END
  END window_o[39]
  PIN window_o[3]
    DIRECTION OUTPUT ;
    USE SIGNAL ;
    PORT
      LAYER Metal3 ;
        RECT  1899.6 1150.18 1900 1150.58 ;
    END
  END window_o[3]
  PIN window_o[40]
    DIRECTION OUTPUT ;
    USE SIGNAL ;
    PORT
      LAYER Metal3 ;
        RECT  1899.6 1243.42 1900 1243.82 ;
    END
  END window_o[40]
  PIN window_o[41]
    DIRECTION OUTPUT ;
    USE SIGNAL ;
    PORT
      LAYER Metal3 ;
        RECT  1899.6 1245.94 1900 1246.34 ;
    END
  END window_o[41]
  PIN window_o[42]
    DIRECTION OUTPUT ;
    USE SIGNAL ;
    PORT
      LAYER Metal3 ;
        RECT  1899.6 1248.46 1900 1248.86 ;
    END
  END window_o[42]
  PIN window_o[43]
    DIRECTION OUTPUT ;
    USE SIGNAL ;
    PORT
      LAYER Metal3 ;
        RECT  1899.6 1250.98 1900 1251.38 ;
    END
  END window_o[43]
  PIN window_o[44]
    DIRECTION OUTPUT ;
    USE SIGNAL ;
    PORT
      LAYER Metal3 ;
        RECT  1899.6 1253.5 1900 1253.9 ;
    END
  END window_o[44]
  PIN window_o[45]
    DIRECTION OUTPUT ;
    USE SIGNAL ;
    PORT
      LAYER Metal3 ;
        RECT  1899.6 1256.02 1900 1256.42 ;
    END
  END window_o[45]
  PIN window_o[46]
    DIRECTION OUTPUT ;
    USE SIGNAL ;
    PORT
      LAYER Metal3 ;
        RECT  1899.6 1258.54 1900 1258.94 ;
    END
  END window_o[46]
  PIN window_o[47]
    DIRECTION OUTPUT ;
    USE SIGNAL ;
    PORT
      LAYER Metal3 ;
        RECT  1899.6 1261.06 1900 1261.46 ;
    END
  END window_o[47]
  PIN window_o[48]
    DIRECTION OUTPUT ;
    USE SIGNAL ;
    PORT
      LAYER Metal3 ;
        RECT  1899.6 1263.58 1900 1263.98 ;
    END
  END window_o[48]
  PIN window_o[49]
    DIRECTION OUTPUT ;
    USE SIGNAL ;
    PORT
      LAYER Metal3 ;
        RECT  1899.6 1266.1 1900 1266.5 ;
    END
  END window_o[49]
  PIN window_o[4]
    DIRECTION OUTPUT ;
    USE SIGNAL ;
    PORT
      LAYER Metal3 ;
        RECT  1899.6 1152.7 1900 1153.1 ;
    END
  END window_o[4]
  PIN window_o[50]
    DIRECTION OUTPUT ;
    USE SIGNAL ;
    PORT
      LAYER Metal3 ;
        RECT  1899.6 1268.62 1900 1269.02 ;
    END
  END window_o[50]
  PIN window_o[51]
    DIRECTION OUTPUT ;
    USE SIGNAL ;
    PORT
      LAYER Metal3 ;
        RECT  1899.6 1271.14 1900 1271.54 ;
    END
  END window_o[51]
  PIN window_o[52]
    DIRECTION OUTPUT ;
    USE SIGNAL ;
    PORT
      LAYER Metal3 ;
        RECT  1899.6 1273.66 1900 1274.06 ;
    END
  END window_o[52]
  PIN window_o[53]
    DIRECTION OUTPUT ;
    USE SIGNAL ;
    PORT
      LAYER Metal3 ;
        RECT  1899.6 1276.18 1900 1276.58 ;
    END
  END window_o[53]
  PIN window_o[54]
    DIRECTION OUTPUT ;
    USE SIGNAL ;
    PORT
      LAYER Metal3 ;
        RECT  1899.6 1278.7 1900 1279.1 ;
    END
  END window_o[54]
  PIN window_o[55]
    DIRECTION OUTPUT ;
    USE SIGNAL ;
    PORT
      LAYER Metal3 ;
        RECT  1899.6 1281.22 1900 1281.62 ;
    END
  END window_o[55]
  PIN window_o[56]
    DIRECTION OUTPUT ;
    USE SIGNAL ;
    PORT
      LAYER Metal3 ;
        RECT  1899.6 1283.74 1900 1284.14 ;
    END
  END window_o[56]
  PIN window_o[57]
    DIRECTION OUTPUT ;
    USE SIGNAL ;
    PORT
      LAYER Metal3 ;
        RECT  1899.6 1286.26 1900 1286.66 ;
    END
  END window_o[57]
  PIN window_o[58]
    DIRECTION OUTPUT ;
    USE SIGNAL ;
    PORT
      LAYER Metal3 ;
        RECT  1899.6 1288.78 1900 1289.18 ;
    END
  END window_o[58]
  PIN window_o[59]
    DIRECTION OUTPUT ;
    USE SIGNAL ;
    PORT
      LAYER Metal3 ;
        RECT  1899.6 1291.3 1900 1291.7 ;
    END
  END window_o[59]
  PIN window_o[5]
    DIRECTION OUTPUT ;
    USE SIGNAL ;
    PORT
      LAYER Metal3 ;
        RECT  1899.6 1155.22 1900 1155.62 ;
    END
  END window_o[5]
  PIN window_o[60]
    DIRECTION OUTPUT ;
    USE SIGNAL ;
    PORT
      LAYER Metal3 ;
        RECT  1899.6 1293.82 1900 1294.22 ;
    END
  END window_o[60]
  PIN window_o[61]
    DIRECTION OUTPUT ;
    USE SIGNAL ;
    PORT
      LAYER Metal3 ;
        RECT  1899.6 1296.34 1900 1296.74 ;
    END
  END window_o[61]
  PIN window_o[62]
    DIRECTION OUTPUT ;
    USE SIGNAL ;
    PORT
      LAYER Metal3 ;
        RECT  1899.6 1298.86 1900 1299.26 ;
    END
  END window_o[62]
  PIN window_o[63]
    DIRECTION OUTPUT ;
    USE SIGNAL ;
    PORT
      LAYER Metal3 ;
        RECT  1899.6 1301.38 1900 1301.78 ;
    END
  END window_o[63]
  PIN window_o[64]
    DIRECTION OUTPUT ;
    USE SIGNAL ;
    PORT
      LAYER Metal3 ;
        RECT  1899.6 1303.9 1900 1304.3 ;
    END
  END window_o[64]
  PIN window_o[65]
    DIRECTION OUTPUT ;
    USE SIGNAL ;
    PORT
      LAYER Metal3 ;
        RECT  1899.6 1306.42 1900 1306.82 ;
    END
  END window_o[65]
  PIN window_o[66]
    DIRECTION OUTPUT ;
    USE SIGNAL ;
    PORT
      LAYER Metal3 ;
        RECT  1899.6 1308.94 1900 1309.34 ;
    END
  END window_o[66]
  PIN window_o[67]
    DIRECTION OUTPUT ;
    USE SIGNAL ;
    PORT
      LAYER Metal3 ;
        RECT  1899.6 1311.46 1900 1311.86 ;
    END
  END window_o[67]
  PIN window_o[68]
    DIRECTION OUTPUT ;
    USE SIGNAL ;
    PORT
      LAYER Metal3 ;
        RECT  1899.6 1313.98 1900 1314.38 ;
    END
  END window_o[68]
  PIN window_o[69]
    DIRECTION OUTPUT ;
    USE SIGNAL ;
    PORT
      LAYER Metal3 ;
        RECT  1899.6 1316.5 1900 1316.9 ;
    END
  END window_o[69]
  PIN window_o[6]
    DIRECTION OUTPUT ;
    USE SIGNAL ;
    PORT
      LAYER Metal3 ;
        RECT  1899.6 1157.74 1900 1158.14 ;
    END
  END window_o[6]
  PIN window_o[70]
    DIRECTION OUTPUT ;
    USE SIGNAL ;
    PORT
      LAYER Metal3 ;
        RECT  1899.6 1319.02 1900 1319.42 ;
    END
  END window_o[70]
  PIN window_o[71]
    DIRECTION OUTPUT ;
    USE SIGNAL ;
    PORT
      LAYER Metal3 ;
        RECT  1899.6 1321.54 1900 1321.94 ;
    END
  END window_o[71]
  PIN window_o[72]
    DIRECTION OUTPUT ;
    USE SIGNAL ;
    PORT
      LAYER Metal3 ;
        RECT  1899.6 1324.06 1900 1324.46 ;
    END
  END window_o[72]
  PIN window_o[73]
    DIRECTION OUTPUT ;
    USE SIGNAL ;
    PORT
      LAYER Metal3 ;
        RECT  1899.6 1326.58 1900 1326.98 ;
    END
  END window_o[73]
  PIN window_o[74]
    DIRECTION OUTPUT ;
    USE SIGNAL ;
    PORT
      LAYER Metal3 ;
        RECT  1899.6 1329.1 1900 1329.5 ;
    END
  END window_o[74]
  PIN window_o[75]
    DIRECTION OUTPUT ;
    USE SIGNAL ;
    PORT
      LAYER Metal3 ;
        RECT  1899.6 1331.62 1900 1332.02 ;
    END
  END window_o[75]
  PIN window_o[76]
    DIRECTION OUTPUT ;
    USE SIGNAL ;
    PORT
      LAYER Metal3 ;
        RECT  1899.6 1334.14 1900 1334.54 ;
    END
  END window_o[76]
  PIN window_o[77]
    DIRECTION OUTPUT ;
    USE SIGNAL ;
    PORT
      LAYER Metal3 ;
        RECT  1899.6 1336.66 1900 1337.06 ;
    END
  END window_o[77]
  PIN window_o[78]
    DIRECTION OUTPUT ;
    USE SIGNAL ;
    PORT
      LAYER Metal3 ;
        RECT  1899.6 1339.18 1900 1339.58 ;
    END
  END window_o[78]
  PIN window_o[79]
    DIRECTION OUTPUT ;
    USE SIGNAL ;
    PORT
      LAYER Metal3 ;
        RECT  1899.6 1341.7 1900 1342.1 ;
    END
  END window_o[79]
  PIN window_o[7]
    DIRECTION OUTPUT ;
    USE SIGNAL ;
    PORT
      LAYER Metal3 ;
        RECT  1899.6 1160.26 1900 1160.66 ;
    END
  END window_o[7]
  PIN window_o[80]
    DIRECTION OUTPUT ;
    USE SIGNAL ;
    PORT
      LAYER Metal3 ;
        RECT  1899.6 1344.22 1900 1344.62 ;
    END
  END window_o[80]
  PIN window_o[81]
    DIRECTION OUTPUT ;
    USE SIGNAL ;
    PORT
      LAYER Metal3 ;
        RECT  1899.6 1346.74 1900 1347.14 ;
    END
  END window_o[81]
  PIN window_o[82]
    DIRECTION OUTPUT ;
    USE SIGNAL ;
    PORT
      LAYER Metal3 ;
        RECT  1899.6 1349.26 1900 1349.66 ;
    END
  END window_o[82]
  PIN window_o[83]
    DIRECTION OUTPUT ;
    USE SIGNAL ;
    PORT
      LAYER Metal3 ;
        RECT  1899.6 1351.78 1900 1352.18 ;
    END
  END window_o[83]
  PIN window_o[84]
    DIRECTION OUTPUT ;
    USE SIGNAL ;
    PORT
      LAYER Metal3 ;
        RECT  1899.6 1354.3 1900 1354.7 ;
    END
  END window_o[84]
  PIN window_o[85]
    DIRECTION OUTPUT ;
    USE SIGNAL ;
    PORT
      LAYER Metal3 ;
        RECT  1899.6 1356.82 1900 1357.22 ;
    END
  END window_o[85]
  PIN window_o[86]
    DIRECTION OUTPUT ;
    USE SIGNAL ;
    PORT
      LAYER Metal3 ;
        RECT  1899.6 1359.34 1900 1359.74 ;
    END
  END window_o[86]
  PIN window_o[87]
    DIRECTION OUTPUT ;
    USE SIGNAL ;
    PORT
      LAYER Metal3 ;
        RECT  1899.6 1361.86 1900 1362.26 ;
    END
  END window_o[87]
  PIN window_o[88]
    DIRECTION OUTPUT ;
    USE SIGNAL ;
    PORT
      LAYER Metal3 ;
        RECT  1899.6 1364.38 1900 1364.78 ;
    END
  END window_o[88]
  PIN window_o[89]
    DIRECTION OUTPUT ;
    USE SIGNAL ;
    PORT
      LAYER Metal3 ;
        RECT  1899.6 1366.9 1900 1367.3 ;
    END
  END window_o[89]
  PIN window_o[8]
    DIRECTION OUTPUT ;
    USE SIGNAL ;
    PORT
      LAYER Metal3 ;
        RECT  1899.6 1162.78 1900 1163.18 ;
    END
  END window_o[8]
  PIN window_o[90]
    DIRECTION OUTPUT ;
    USE SIGNAL ;
    PORT
      LAYER Metal3 ;
        RECT  1899.6 1369.42 1900 1369.82 ;
    END
  END window_o[90]
  PIN window_o[91]
    DIRECTION OUTPUT ;
    USE SIGNAL ;
    PORT
      LAYER Metal3 ;
        RECT  1899.6 1371.94 1900 1372.34 ;
    END
  END window_o[91]
  PIN window_o[92]
    DIRECTION OUTPUT ;
    USE SIGNAL ;
    PORT
      LAYER Metal3 ;
        RECT  1899.6 1374.46 1900 1374.86 ;
    END
  END window_o[92]
  PIN window_o[93]
    DIRECTION OUTPUT ;
    USE SIGNAL ;
    PORT
      LAYER Metal3 ;
        RECT  1899.6 1376.98 1900 1377.38 ;
    END
  END window_o[93]
  PIN window_o[94]
    DIRECTION OUTPUT ;
    USE SIGNAL ;
    PORT
      LAYER Metal3 ;
        RECT  1899.6 1379.5 1900 1379.9 ;
    END
  END window_o[94]
  PIN window_o[95]
    DIRECTION OUTPUT ;
    USE SIGNAL ;
    PORT
      LAYER Metal3 ;
        RECT  1899.6 1382.02 1900 1382.42 ;
    END
  END window_o[95]
  PIN window_o[96]
    DIRECTION OUTPUT ;
    USE SIGNAL ;
    PORT
      LAYER Metal3 ;
        RECT  1899.6 1384.54 1900 1384.94 ;
    END
  END window_o[96]
  PIN window_o[97]
    DIRECTION OUTPUT ;
    USE SIGNAL ;
    PORT
      LAYER Metal3 ;
        RECT  1899.6 1387.06 1900 1387.46 ;
    END
  END window_o[97]
  PIN window_o[98]
    DIRECTION OUTPUT ;
    USE SIGNAL ;
    PORT
      LAYER Metal3 ;
        RECT  1899.6 1389.58 1900 1389.98 ;
    END
  END window_o[98]
  PIN window_o[99]
    DIRECTION OUTPUT ;
    USE SIGNAL ;
    PORT
      LAYER Metal3 ;
        RECT  1899.6 1392.1 1900 1392.5 ;
    END
  END window_o[99]
  PIN window_o[9]
    DIRECTION OUTPUT ;
    USE SIGNAL ;
    PORT
      LAYER Metal3 ;
        RECT  1899.6 1165.3 1900 1165.7 ;
    END
  END window_o[9]
  PIN window_pc_o[0]
    DIRECTION OUTPUT ;
    USE SIGNAL ;
    PORT
      LAYER Metal3 ;
        RECT  1899.6 1883.5 1900 1883.9 ;
    END
  END window_pc_o[0]
  PIN window_pc_o[10]
    DIRECTION OUTPUT ;
    USE SIGNAL ;
    PORT
      LAYER Metal3 ;
        RECT  1899.6 1908.7 1900 1909.1 ;
    END
  END window_pc_o[10]
  PIN window_pc_o[11]
    DIRECTION OUTPUT ;
    USE SIGNAL ;
    PORT
      LAYER Metal3 ;
        RECT  1899.6 1911.22 1900 1911.62 ;
    END
  END window_pc_o[11]
  PIN window_pc_o[12]
    DIRECTION OUTPUT ;
    USE SIGNAL ;
    PORT
      LAYER Metal3 ;
        RECT  1899.6 1913.74 1900 1914.14 ;
    END
  END window_pc_o[12]
  PIN window_pc_o[13]
    DIRECTION OUTPUT ;
    USE SIGNAL ;
    PORT
      LAYER Metal3 ;
        RECT  1899.6 1916.26 1900 1916.66 ;
    END
  END window_pc_o[13]
  PIN window_pc_o[14]
    DIRECTION OUTPUT ;
    USE SIGNAL ;
    PORT
      LAYER Metal3 ;
        RECT  1899.6 1918.78 1900 1919.18 ;
    END
  END window_pc_o[14]
  PIN window_pc_o[15]
    DIRECTION OUTPUT ;
    USE SIGNAL ;
    PORT
      LAYER Metal3 ;
        RECT  1899.6 1921.3 1900 1921.7 ;
    END
  END window_pc_o[15]
  PIN window_pc_o[16]
    DIRECTION OUTPUT ;
    USE SIGNAL ;
    PORT
      LAYER Metal3 ;
        RECT  1899.6 1923.82 1900 1924.22 ;
    END
  END window_pc_o[16]
  PIN window_pc_o[17]
    DIRECTION OUTPUT ;
    USE SIGNAL ;
    PORT
      LAYER Metal3 ;
        RECT  1899.6 1926.34 1900 1926.74 ;
    END
  END window_pc_o[17]
  PIN window_pc_o[18]
    DIRECTION OUTPUT ;
    USE SIGNAL ;
    PORT
      LAYER Metal3 ;
        RECT  1899.6 1928.86 1900 1929.26 ;
    END
  END window_pc_o[18]
  PIN window_pc_o[19]
    DIRECTION OUTPUT ;
    USE SIGNAL ;
    PORT
      LAYER Metal3 ;
        RECT  1899.6 1931.38 1900 1931.78 ;
    END
  END window_pc_o[19]
  PIN window_pc_o[1]
    DIRECTION OUTPUT ;
    USE SIGNAL ;
    PORT
      LAYER Metal3 ;
        RECT  1899.6 1886.02 1900 1886.42 ;
    END
  END window_pc_o[1]
  PIN window_pc_o[20]
    DIRECTION OUTPUT ;
    USE SIGNAL ;
    PORT
      LAYER Metal3 ;
        RECT  1899.6 1933.9 1900 1934.3 ;
    END
  END window_pc_o[20]
  PIN window_pc_o[21]
    DIRECTION OUTPUT ;
    USE SIGNAL ;
    PORT
      LAYER Metal3 ;
        RECT  1899.6 1936.42 1900 1936.82 ;
    END
  END window_pc_o[21]
  PIN window_pc_o[22]
    DIRECTION OUTPUT ;
    USE SIGNAL ;
    PORT
      LAYER Metal3 ;
        RECT  1899.6 1938.94 1900 1939.34 ;
    END
  END window_pc_o[22]
  PIN window_pc_o[23]
    DIRECTION OUTPUT ;
    USE SIGNAL ;
    PORT
      LAYER Metal3 ;
        RECT  1899.6 1941.46 1900 1941.86 ;
    END
  END window_pc_o[23]
  PIN window_pc_o[24]
    DIRECTION OUTPUT ;
    USE SIGNAL ;
    PORT
      LAYER Metal3 ;
        RECT  1899.6 1943.98 1900 1944.38 ;
    END
  END window_pc_o[24]
  PIN window_pc_o[25]
    DIRECTION OUTPUT ;
    USE SIGNAL ;
    PORT
      LAYER Metal3 ;
        RECT  1899.6 1946.5 1900 1946.9 ;
    END
  END window_pc_o[25]
  PIN window_pc_o[26]
    DIRECTION OUTPUT ;
    USE SIGNAL ;
    PORT
      LAYER Metal3 ;
        RECT  1899.6 1949.02 1900 1949.42 ;
    END
  END window_pc_o[26]
  PIN window_pc_o[27]
    DIRECTION OUTPUT ;
    USE SIGNAL ;
    PORT
      LAYER Metal3 ;
        RECT  1899.6 1951.54 1900 1951.94 ;
    END
  END window_pc_o[27]
  PIN window_pc_o[28]
    DIRECTION OUTPUT ;
    USE SIGNAL ;
    PORT
      LAYER Metal3 ;
        RECT  1899.6 1954.06 1900 1954.46 ;
    END
  END window_pc_o[28]
  PIN window_pc_o[29]
    DIRECTION OUTPUT ;
    USE SIGNAL ;
    PORT
      LAYER Metal3 ;
        RECT  1899.6 1956.58 1900 1956.98 ;
    END
  END window_pc_o[29]
  PIN window_pc_o[2]
    DIRECTION OUTPUT ;
    USE SIGNAL ;
    PORT
      LAYER Metal3 ;
        RECT  1899.6 1888.54 1900 1888.94 ;
    END
  END window_pc_o[2]
  PIN window_pc_o[30]
    DIRECTION OUTPUT ;
    USE SIGNAL ;
    PORT
      LAYER Metal3 ;
        RECT  1899.6 1959.1 1900 1959.5 ;
    END
  END window_pc_o[30]
  PIN window_pc_o[31]
    DIRECTION OUTPUT ;
    USE SIGNAL ;
    PORT
      LAYER Metal3 ;
        RECT  1899.6 1961.62 1900 1962.02 ;
    END
  END window_pc_o[31]
  PIN window_pc_o[3]
    DIRECTION OUTPUT ;
    USE SIGNAL ;
    PORT
      LAYER Metal3 ;
        RECT  1899.6 1891.06 1900 1891.46 ;
    END
  END window_pc_o[3]
  PIN window_pc_o[4]
    DIRECTION OUTPUT ;
    USE SIGNAL ;
    PORT
      LAYER Metal3 ;
        RECT  1899.6 1893.58 1900 1893.98 ;
    END
  END window_pc_o[4]
  PIN window_pc_o[5]
    DIRECTION OUTPUT ;
    USE SIGNAL ;
    PORT
      LAYER Metal3 ;
        RECT  1899.6 1896.1 1900 1896.5 ;
    END
  END window_pc_o[5]
  PIN window_pc_o[6]
    DIRECTION OUTPUT ;
    USE SIGNAL ;
    PORT
      LAYER Metal3 ;
        RECT  1899.6 1898.62 1900 1899.02 ;
    END
  END window_pc_o[6]
  PIN window_pc_o[7]
    DIRECTION OUTPUT ;
    USE SIGNAL ;
    PORT
      LAYER Metal3 ;
        RECT  1899.6 1901.14 1900 1901.54 ;
    END
  END window_pc_o[7]
  PIN window_pc_o[8]
    DIRECTION OUTPUT ;
    USE SIGNAL ;
    PORT
      LAYER Metal3 ;
        RECT  1899.6 1903.66 1900 1904.06 ;
    END
  END window_pc_o[8]
  PIN window_pc_o[9]
    DIRECTION OUTPUT ;
    USE SIGNAL ;
    PORT
      LAYER Metal3 ;
        RECT  1899.6 1906.18 1900 1906.58 ;
    END
  END window_pc_o[9]
  PIN VPWR
    DIRECTION INOUT ;
    USE POWER ;
    PORT
      LAYER TopMetal1 ;
        RECT  5.76 2174.12 1894.08 2176.12 ;
        RECT  5.76 2124.12 1894.08 2126.12 ;
        RECT  5.76 2074.12 1894.08 2076.12 ;
        RECT  5.76 2024.12 1894.08 2026.12 ;
        RECT  5.76 1974.12 1894.08 1976.12 ;
        RECT  5.76 1924.12 1894.08 1926.12 ;
        RECT  5.76 1874.12 1894.08 1876.12 ;
        RECT  5.76 1824.12 1894.08 1826.12 ;
        RECT  5.76 1774.12 1894.08 1776.12 ;
        RECT  5.76 1724.12 1894.08 1726.12 ;
        RECT  5.76 1674.12 1894.08 1676.12 ;
        RECT  5.76 1624.12 1894.08 1626.12 ;
        RECT  5.76 1574.12 1894.08 1576.12 ;
        RECT  5.76 1524.12 1894.08 1526.12 ;
        RECT  5.76 1474.12 1894.08 1476.12 ;
        RECT  5.76 1424.12 1894.08 1426.12 ;
        RECT  5.76 1374.12 1894.08 1376.12 ;
        RECT  5.76 1324.12 1894.08 1326.12 ;
        RECT  5.76 1274.12 1894.08 1276.12 ;
        RECT  5.76 1224.12 1894.08 1226.12 ;
        RECT  5.76 1174.12 1894.08 1176.12 ;
        RECT  5.76 1124.12 1894.08 1126.12 ;
        RECT  5.76 1074.12 1894.08 1076.12 ;
        RECT  5.76 1024.12 1894.08 1026.12 ;
        RECT  5.76 974.12 1894.08 976.12 ;
        RECT  5.76 924.12 1894.08 926.12 ;
        RECT  5.76 874.12 1894.08 876.12 ;
        RECT  5.76 824.12 1894.08 826.12 ;
        RECT  5.76 774.12 1894.08 776.12 ;
        RECT  5.76 724.12 1894.08 726.12 ;
        RECT  5.76 674.12 1894.08 676.12 ;
        RECT  5.76 624.12 1894.08 626.12 ;
        RECT  5.76 574.12 1894.08 576.12 ;
        RECT  5.76 524.12 1894.08 526.12 ;
        RECT  5.76 474.12 1894.08 476.12 ;
        RECT  5.76 424.12 1894.08 426.12 ;
        RECT  5.76 374.12 1894.08 376.12 ;
        RECT  5.76 324.12 1894.08 326.12 ;
        RECT  5.76 274.12 1894.08 276.12 ;
        RECT  5.76 224.12 1894.08 226.12 ;
        RECT  5.76 174.12 1894.08 176.12 ;
        RECT  5.76 124.12 1894.08 126.12 ;
        RECT  5.76 74.12 1894.08 76.12 ;
        RECT  5.76 24.12 1894.08 26.12 ;
      LAYER Metal4 ;
        RECT  1865.26 14.9 1866.26 2185.06 ;
        RECT  1815.26 1979.65 1816.26 2185.06 ;
        RECT  1815.26 14.9 1816.26 1739.4 ;
        RECT  1765.26 1979.89 1766.26 2185.06 ;
        RECT  1765.26 1710.25 1766.26 1739.16 ;
        RECT  1765.26 14.9 1766.26 1469.52 ;
        RECT  1715.26 1979.89 1716.26 2185.06 ;
        RECT  1715.26 1710.25 1716.26 1739.16 ;
        RECT  1715.26 14.9 1716.26 1469.52 ;
        RECT  1665.26 1979.65 1666.26 2185.06 ;
        RECT  1665.26 1710.01 1666.26 1739.4 ;
        RECT  1665.26 322.25 1666.26 1469.76 ;
        RECT  1665.26 14.9 1666.26 81.52 ;
        RECT  1615.26 1979.89 1616.26 2185.06 ;
        RECT  1615.26 1710.25 1616.26 1739.16 ;
        RECT  1615.26 1129.97 1616.26 1469.52 ;
        RECT  1615.26 714.2 1616.26 889.24 ;
        RECT  1615.26 322.25 1616.26 473.52 ;
        RECT  1615.26 14.9 1616.26 81.52 ;
        RECT  1565.26 1979.89 1566.26 2185.06 ;
        RECT  1565.26 1710.25 1566.26 1739.16 ;
        RECT  1565.26 1129.97 1566.26 1469.52 ;
        RECT  1565.26 714.2 1566.26 889.24 ;
        RECT  1565.26 322.01 1566.26 473.52 ;
        RECT  1565.26 14.9 1566.26 81.76 ;
        RECT  1515.26 1979.65 1516.26 2185.06 ;
        RECT  1515.26 1710.01 1516.26 1739.4 ;
        RECT  1515.26 1129.73 1516.26 1469.76 ;
        RECT  1515.26 714.01 1516.26 889.48 ;
        RECT  1515.26 322.25 1516.26 473.76 ;
        RECT  1515.26 14.9 1516.26 81.52 ;
        RECT  1465.26 1979.89 1466.26 2185.06 ;
        RECT  1465.26 1710.25 1466.26 1739.16 ;
        RECT  1465.26 1129.97 1466.26 1469.52 ;
        RECT  1465.26 714.2 1466.26 889.24 ;
        RECT  1465.26 322.25 1466.26 473.52 ;
        RECT  1465.26 14.9 1466.26 81.52 ;
        RECT  1415.26 1979.65 1416.26 2185.06 ;
        RECT  1415.26 1710.25 1416.26 1739.4 ;
        RECT  1415.26 1129.97 1416.26 1469.52 ;
        RECT  1415.26 714.2 1416.26 889.24 ;
        RECT  1415.26 322.01 1416.26 473.52 ;
        RECT  1415.26 14.9 1416.26 81.76 ;
        RECT  1365.26 1979.89 1366.26 2185.06 ;
        RECT  1365.26 1710.25 1366.26 1739.16 ;
        RECT  1365.26 1129.73 1366.26 1469.52 ;
        RECT  1365.26 714.01 1366.26 889.48 ;
        RECT  1365.26 322.25 1366.26 473.76 ;
        RECT  1365.26 14.9 1366.26 81.52 ;
        RECT  1315.26 1979.65 1316.26 2185.06 ;
        RECT  1315.26 1710.01 1316.26 1739.4 ;
        RECT  1315.26 1129.97 1316.26 1469.76 ;
        RECT  1315.26 714.2 1316.26 889.24 ;
        RECT  1315.26 322.25 1316.26 473.52 ;
        RECT  1315.26 14.9 1316.26 81.52 ;
        RECT  1265.26 1979.89 1266.26 2185.06 ;
        RECT  1265.26 1710.25 1266.26 1739.16 ;
        RECT  1265.26 1129.97 1266.26 1469.52 ;
        RECT  1265.26 714.2 1266.26 889.24 ;
        RECT  1265.26 322.25 1266.26 473.52 ;
        RECT  1265.26 14.9 1266.26 81.52 ;
        RECT  1215.26 1979.89 1216.26 2185.06 ;
        RECT  1215.26 1710.25 1216.26 1739.16 ;
        RECT  1215.26 1129.97 1216.26 1469.52 ;
        RECT  1215.26 714.2 1216.26 889.24 ;
        RECT  1215.26 322.01 1216.26 473.52 ;
        RECT  1215.26 14.9 1216.26 81.76 ;
        RECT  1165.26 1979.89 1166.26 2185.06 ;
        RECT  1165.26 1710.01 1166.26 1739.16 ;
        RECT  1165.26 1129.73 1166.26 1469.76 ;
        RECT  1165.26 714.01 1166.26 889.48 ;
        RECT  1165.26 322.25 1166.26 473.76 ;
        RECT  1165.26 14.9 1166.26 81.52 ;
        RECT  1115.26 1979.65 1116.26 2185.06 ;
        RECT  1115.26 1710.25 1116.26 1739.4 ;
        RECT  1115.26 1129.97 1116.26 1469.52 ;
        RECT  1115.26 714.2 1116.26 889.24 ;
        RECT  1115.26 322.25 1116.26 473.52 ;
        RECT  1115.26 14.9 1116.26 81.52 ;
        RECT  1065.26 1129.97 1066.26 2185.06 ;
        RECT  1065.26 714.2 1066.26 889.24 ;
        RECT  1065.26 322.01 1066.26 473.52 ;
        RECT  1065.26 14.9 1066.26 81.76 ;
        RECT  1015.26 1129.73 1016.26 2185.06 ;
        RECT  1015.26 714.01 1016.26 889.48 ;
        RECT  1015.26 322.25 1016.26 473.76 ;
        RECT  1015.26 14.9 1016.26 81.52 ;
        RECT  965.26 1129.97 966.26 2185.06 ;
        RECT  965.26 714.2 966.26 889.24 ;
        RECT  965.26 14.9 966.26 473.52 ;
        RECT  915.26 14.9 916.26 2185.06 ;
        RECT  865.26 14.9 866.26 2185.06 ;
        RECT  815.26 14.9 816.26 2185.06 ;
        RECT  765.26 14.9 766.26 2185.06 ;
        RECT  715.26 2160.25 716.26 2185.06 ;
        RECT  715.26 1786.25 716.26 1919.52 ;
        RECT  715.26 1500.25 716.26 1545.52 ;
        RECT  715.26 1118.25 716.26 1259.52 ;
        RECT  715.26 866.25 716.26 877.52 ;
        RECT  715.26 430.25 716.26 625.52 ;
        RECT  715.26 14.9 716.26 189.52 ;
        RECT  665.26 2160.25 666.26 2185.06 ;
        RECT  665.26 1786.25 666.26 1919.52 ;
        RECT  665.26 1500.25 666.26 1545.52 ;
        RECT  665.26 1118.25 666.26 1259.52 ;
        RECT  665.26 866.25 666.26 877.52 ;
        RECT  665.26 430.25 666.26 625.52 ;
        RECT  665.26 14.9 666.26 189.52 ;
        RECT  615.26 2160.01 616.26 2185.06 ;
        RECT  615.26 1786.01 616.26 1919.76 ;
        RECT  615.26 1500.01 616.26 1545.76 ;
        RECT  615.26 1118.01 616.26 1259.76 ;
        RECT  615.26 866.01 616.26 877.76 ;
        RECT  615.26 430.01 616.26 625.76 ;
        RECT  615.26 14.9 616.26 189.76 ;
        RECT  565.26 2160.25 566.26 2185.06 ;
        RECT  565.26 1786.25 566.26 1919.52 ;
        RECT  565.26 1500.25 566.26 1545.52 ;
        RECT  565.26 1118.25 566.26 1259.52 ;
        RECT  565.26 866.25 566.26 877.52 ;
        RECT  565.26 430.25 566.26 625.52 ;
        RECT  565.26 14.9 566.26 189.52 ;
        RECT  515.26 2160.25 516.26 2185.06 ;
        RECT  515.26 1786.25 516.26 1919.52 ;
        RECT  515.26 1500.25 516.26 1545.52 ;
        RECT  515.26 1118.25 516.26 1259.52 ;
        RECT  515.26 866.25 516.26 877.52 ;
        RECT  515.26 430.25 516.26 625.52 ;
        RECT  515.26 14.9 516.26 189.52 ;
        RECT  465.26 2160.01 466.26 2185.06 ;
        RECT  465.26 1786.01 466.26 1919.76 ;
        RECT  465.26 1500.01 466.26 1545.76 ;
        RECT  465.26 1118.01 466.26 1259.76 ;
        RECT  465.26 866.01 466.26 877.76 ;
        RECT  465.26 430.01 466.26 625.76 ;
        RECT  465.26 14.9 466.26 189.76 ;
        RECT  415.26 2160.25 416.26 2185.06 ;
        RECT  415.26 1786.25 416.26 1919.52 ;
        RECT  415.26 1500.25 416.26 1545.52 ;
        RECT  415.26 1118.25 416.26 1259.52 ;
        RECT  415.26 866.25 416.26 877.52 ;
        RECT  415.26 430.25 416.26 625.52 ;
        RECT  415.26 14.9 416.26 189.52 ;
        RECT  365.26 2160.25 366.26 2185.06 ;
        RECT  365.26 1786.25 366.26 1919.52 ;
        RECT  365.26 1500.25 366.26 1545.52 ;
        RECT  365.26 1118.25 366.26 1259.52 ;
        RECT  365.26 866.25 366.26 877.52 ;
        RECT  365.26 430.25 366.26 625.52 ;
        RECT  365.26 14.9 366.26 189.52 ;
        RECT  315.26 2160.25 316.26 2185.06 ;
        RECT  315.26 1786.25 316.26 1919.52 ;
        RECT  315.26 1500.25 316.26 1545.52 ;
        RECT  315.26 1118.25 316.26 1259.52 ;
        RECT  315.26 866.25 316.26 877.52 ;
        RECT  315.26 430.25 316.26 625.52 ;
        RECT  315.26 14.9 316.26 189.52 ;
        RECT  265.26 2160.01 266.26 2185.06 ;
        RECT  265.26 1786.01 266.26 1919.76 ;
        RECT  265.26 1500.01 266.26 1545.76 ;
        RECT  265.26 1118.01 266.26 1259.76 ;
        RECT  265.26 866.01 266.26 877.76 ;
        RECT  265.26 430.01 266.26 625.76 ;
        RECT  265.26 14.9 266.26 189.76 ;
        RECT  215.26 2160.25 216.26 2185.06 ;
        RECT  215.26 1786.25 216.26 1919.52 ;
        RECT  215.26 1500.25 216.26 1545.52 ;
        RECT  215.26 1118.25 216.26 1259.52 ;
        RECT  215.26 866.25 216.26 877.52 ;
        RECT  215.26 430.25 216.26 625.52 ;
        RECT  215.26 14.9 216.26 189.52 ;
        RECT  165.26 2160.25 166.26 2185.06 ;
        RECT  165.26 1786.25 166.26 1919.52 ;
        RECT  165.26 1500.25 166.26 1545.52 ;
        RECT  165.26 1118.25 166.26 1259.52 ;
        RECT  165.26 866.25 166.26 877.52 ;
        RECT  165.26 430.25 166.26 625.52 ;
        RECT  165.26 14.9 166.26 189.52 ;
        RECT  115.26 2160.01 116.26 2185.06 ;
        RECT  115.26 1786.01 116.26 1919.76 ;
        RECT  115.26 1500.01 116.26 1545.76 ;
        RECT  115.26 1118.01 116.26 1259.76 ;
        RECT  115.26 866.01 116.26 877.76 ;
        RECT  115.26 430.01 116.26 625.76 ;
        RECT  115.26 14.9 116.26 189.76 ;
        RECT  65.26 2160.25 66.26 2185.06 ;
        RECT  65.26 1786.25 66.26 1919.52 ;
        RECT  65.26 1500.25 66.26 1545.52 ;
        RECT  65.26 1118.25 66.26 1259.52 ;
        RECT  65.26 866.25 66.26 877.52 ;
        RECT  65.26 430.25 66.26 625.52 ;
        RECT  65.26 14.9 66.26 189.52 ;
        RECT  15.26 14.9 16.26 2185.06 ;
    END
  END VPWR
  PIN VGND
    DIRECTION INOUT ;
    USE GROUND ;
    PORT
      LAYER TopMetal1 ;
        RECT  18.13 868.425 769.39 870.065 ;
        RECT  5.76 2180.12 1894.08 2182.12 ;
        RECT  5.76 2130.12 1894.08 2132.12 ;
        RECT  5.76 2080.12 1894.08 2082.12 ;
        RECT  5.76 2030.12 1894.08 2032.12 ;
        RECT  5.76 1980.12 1894.08 1982.12 ;
        RECT  5.76 1930.12 1894.08 1932.12 ;
        RECT  5.76 1880.12 1894.08 1882.12 ;
        RECT  5.76 1830.12 1894.08 1832.12 ;
        RECT  5.76 1780.12 1894.08 1782.12 ;
        RECT  5.76 1730.12 1894.08 1732.12 ;
        RECT  5.76 1680.12 1894.08 1682.12 ;
        RECT  5.76 1630.12 1894.08 1632.12 ;
        RECT  5.76 1580.12 1894.08 1582.12 ;
        RECT  5.76 1530.12 1894.08 1532.12 ;
        RECT  5.76 1480.12 1894.08 1482.12 ;
        RECT  5.76 1430.12 1894.08 1432.12 ;
        RECT  5.76 1380.12 1894.08 1382.12 ;
        RECT  5.76 1330.12 1894.08 1332.12 ;
        RECT  5.76 1280.12 1894.08 1282.12 ;
        RECT  5.76 1230.12 1894.08 1232.12 ;
        RECT  5.76 1180.12 1894.08 1182.12 ;
        RECT  5.76 1130.12 1894.08 1132.12 ;
        RECT  5.76 1080.12 1894.08 1082.12 ;
        RECT  5.76 1030.12 1894.08 1032.12 ;
        RECT  5.76 980.12 1894.08 982.12 ;
        RECT  5.76 930.12 1894.08 932.12 ;
        RECT  5.76 880.12 1894.08 882.12 ;
        RECT  5.76 830.12 1894.08 832.12 ;
        RECT  5.76 780.12 1894.08 782.12 ;
        RECT  5.76 730.12 1894.08 732.12 ;
        RECT  5.76 680.12 1894.08 682.12 ;
        RECT  5.76 630.12 1894.08 632.12 ;
        RECT  5.76 580.12 1894.08 582.12 ;
        RECT  5.76 530.12 1894.08 532.12 ;
        RECT  5.76 480.12 1894.08 482.12 ;
        RECT  5.76 430.12 1894.08 432.12 ;
        RECT  5.76 380.12 1894.08 382.12 ;
        RECT  5.76 330.12 1894.08 332.12 ;
        RECT  5.76 280.12 1894.08 282.12 ;
        RECT  5.76 230.12 1894.08 232.12 ;
        RECT  5.76 180.12 1894.08 182.12 ;
        RECT  5.76 130.12 1894.08 132.12 ;
        RECT  5.76 80.12 1894.08 82.12 ;
        RECT  5.76 30.12 1894.08 32.12 ;
      LAYER Metal4 ;
        RECT  1868.26 14.9 1869.26 2185.06 ;
        RECT  1818.26 1979.65 1819.26 2185.06 ;
        RECT  1818.26 14.9 1819.26 1739.4 ;
        RECT  1768.26 1979.89 1769.26 2185.06 ;
        RECT  1768.26 1710.25 1769.26 1739.16 ;
        RECT  1768.26 14.9 1769.26 1469.52 ;
        RECT  1718.26 1979.65 1719.26 2185.06 ;
        RECT  1718.26 1710.01 1719.26 1739.4 ;
        RECT  1718.26 14.9 1719.26 1469.76 ;
        RECT  1668.26 1979.89 1669.26 2185.06 ;
        RECT  1668.26 1710.25 1669.26 1739.16 ;
        RECT  1668.26 322.25 1669.26 1469.52 ;
        RECT  1668.26 14.9 1669.26 81.52 ;
        RECT  1618.26 1979.89 1619.26 2185.06 ;
        RECT  1618.26 1710.25 1619.26 1739.16 ;
        RECT  1618.26 1129.97 1619.26 1469.52 ;
        RECT  1618.26 714.25 1619.26 889.24 ;
        RECT  1618.26 322.01 1619.26 473.52 ;
        RECT  1618.26 14.9 1619.26 81.76 ;
        RECT  1568.26 1979.65 1569.26 2185.06 ;
        RECT  1568.26 1710.01 1569.26 1739.4 ;
        RECT  1568.26 1129.73 1569.26 1469.76 ;
        RECT  1568.26 714.01 1569.26 889.48 ;
        RECT  1568.26 322.25 1569.26 473.76 ;
        RECT  1568.26 14.9 1569.26 81.52 ;
        RECT  1518.26 1979.65 1519.26 2185.06 ;
        RECT  1518.26 1710.25 1519.26 1739.4 ;
        RECT  1518.26 1129.97 1519.26 1469.52 ;
        RECT  1518.26 714.25 1519.26 889.24 ;
        RECT  1518.26 322.25 1519.26 473.52 ;
        RECT  1518.26 14.9 1519.26 81.52 ;
        RECT  1468.26 1979.89 1469.26 2185.06 ;
        RECT  1468.26 1710.25 1469.26 1739.16 ;
        RECT  1468.26 1129.97 1469.26 1469.52 ;
        RECT  1468.26 714.25 1469.26 889.24 ;
        RECT  1468.26 322.01 1469.26 473.52 ;
        RECT  1468.26 14.9 1469.26 81.76 ;
        RECT  1418.26 1979.65 1419.26 2185.06 ;
        RECT  1418.26 1710.25 1419.26 1739.4 ;
        RECT  1418.26 1129.73 1419.26 1469.52 ;
        RECT  1418.26 714.01 1419.26 889.48 ;
        RECT  1418.26 322.25 1419.26 473.76 ;
        RECT  1418.26 14.9 1419.26 81.52 ;
        RECT  1368.26 1979.65 1369.26 2185.06 ;
        RECT  1368.26 1710.01 1369.26 1739.4 ;
        RECT  1368.26 1129.97 1369.26 1469.76 ;
        RECT  1368.26 714.25 1369.26 889.24 ;
        RECT  1368.26 322.25 1369.26 473.52 ;
        RECT  1368.26 14.9 1369.26 81.52 ;
        RECT  1318.26 1979.89 1319.26 2185.06 ;
        RECT  1318.26 1710.25 1319.26 1739.16 ;
        RECT  1318.26 1129.97 1319.26 1469.52 ;
        RECT  1318.26 714.25 1319.26 889.24 ;
        RECT  1318.26 322.25 1319.26 473.52 ;
        RECT  1318.26 14.9 1319.26 81.52 ;
        RECT  1268.26 1979.89 1269.26 2185.06 ;
        RECT  1268.26 1710.25 1269.26 1739.16 ;
        RECT  1268.26 1129.97 1269.26 1469.52 ;
        RECT  1268.26 714.25 1269.26 889.24 ;
        RECT  1268.26 322.01 1269.26 473.52 ;
        RECT  1268.26 14.9 1269.26 81.76 ;
        RECT  1218.26 1979.89 1219.26 2185.06 ;
        RECT  1218.26 1710.01 1219.26 1739.16 ;
        RECT  1218.26 1129.73 1219.26 1469.76 ;
        RECT  1218.26 714.01 1219.26 889.48 ;
        RECT  1218.26 322.25 1219.26 473.76 ;
        RECT  1218.26 14.9 1219.26 81.52 ;
        RECT  1168.26 1979.89 1169.26 2185.06 ;
        RECT  1168.26 1710.25 1169.26 1739.16 ;
        RECT  1168.26 1129.97 1169.26 1469.52 ;
        RECT  1168.26 714.25 1169.26 889.24 ;
        RECT  1168.26 322.25 1169.26 473.52 ;
        RECT  1168.26 14.9 1169.26 81.52 ;
        RECT  1118.26 1979.65 1119.26 2185.06 ;
        RECT  1118.26 1710.25 1119.26 1739.4 ;
        RECT  1118.26 1129.97 1119.26 1469.52 ;
        RECT  1118.26 714.25 1119.26 889.24 ;
        RECT  1118.26 322.01 1119.26 473.52 ;
        RECT  1118.26 14.9 1119.26 81.76 ;
        RECT  1068.26 1129.73 1069.26 2185.06 ;
        RECT  1068.26 714.01 1069.26 889.48 ;
        RECT  1068.26 322.25 1069.26 473.76 ;
        RECT  1068.26 14.9 1069.26 81.52 ;
        RECT  1018.26 1129.97 1019.26 2185.06 ;
        RECT  1018.26 714.25 1019.26 889.24 ;
        RECT  1018.26 322.25 1019.26 473.52 ;
        RECT  1018.26 14.9 1019.26 81.52 ;
        RECT  968.26 1129.97 969.26 2185.06 ;
        RECT  968.26 714.25 969.26 889.24 ;
        RECT  968.26 14.9 969.26 473.52 ;
        RECT  918.26 14.9 919.26 2185.06 ;
        RECT  868.26 14.9 869.26 2185.06 ;
        RECT  818.26 14.9 819.26 2185.06 ;
        RECT  768.26 14.9 769.26 2185.06 ;
        RECT  718.26 2160.25 719.26 2185.06 ;
        RECT  718.26 1786.25 719.26 1919.52 ;
        RECT  718.26 1500.25 719.26 1545.52 ;
        RECT  718.26 1118.25 719.26 1259.52 ;
        RECT  718.26 866.25 719.26 877.52 ;
        RECT  718.26 430.12 719.26 625.52 ;
        RECT  718.26 14.9 719.26 189.52 ;
        RECT  668.26 2160.01 669.26 2185.06 ;
        RECT  668.26 1786.01 669.26 1919.76 ;
        RECT  668.26 1500.01 669.26 1545.76 ;
        RECT  668.26 1118.01 669.26 1259.76 ;
        RECT  668.26 866.01 669.26 877.76 ;
        RECT  668.26 430.01 669.26 625.76 ;
        RECT  668.26 14.9 669.26 189.76 ;
        RECT  618.26 2160.25 619.26 2185.06 ;
        RECT  618.26 1786.25 619.26 1919.52 ;
        RECT  618.26 1500.25 619.26 1545.52 ;
        RECT  618.26 1118.25 619.26 1259.52 ;
        RECT  618.26 866.25 619.26 877.52 ;
        RECT  618.26 430.12 619.26 625.52 ;
        RECT  618.26 14.9 619.26 189.52 ;
        RECT  568.26 2160.25 569.26 2185.06 ;
        RECT  568.26 1786.25 569.26 1919.52 ;
        RECT  568.26 1500.25 569.26 1545.52 ;
        RECT  568.26 1118.25 569.26 1259.52 ;
        RECT  568.26 866.25 569.26 877.52 ;
        RECT  568.26 430.12 569.26 625.52 ;
        RECT  568.26 14.9 569.26 189.52 ;
        RECT  518.26 2160.01 519.26 2185.06 ;
        RECT  518.26 1786.01 519.26 1919.76 ;
        RECT  518.26 1500.01 519.26 1545.76 ;
        RECT  518.26 1118.01 519.26 1259.76 ;
        RECT  518.26 866.01 519.26 877.76 ;
        RECT  518.26 430.01 519.26 625.76 ;
        RECT  518.26 14.9 519.26 189.76 ;
        RECT  468.26 2160.25 469.26 2185.06 ;
        RECT  468.26 1786.25 469.26 1919.52 ;
        RECT  468.26 1500.25 469.26 1545.52 ;
        RECT  468.26 1118.25 469.26 1259.52 ;
        RECT  468.26 866.25 469.26 877.52 ;
        RECT  468.26 430.12 469.26 625.52 ;
        RECT  468.26 14.9 469.26 189.52 ;
        RECT  418.26 2160.25 419.26 2185.06 ;
        RECT  418.26 1786.25 419.26 1919.52 ;
        RECT  418.26 1500.25 419.26 1545.52 ;
        RECT  418.26 1118.25 419.26 1259.52 ;
        RECT  418.26 866.25 419.26 877.52 ;
        RECT  418.26 430.12 419.26 625.52 ;
        RECT  418.26 14.9 419.26 189.52 ;
        RECT  368.26 2160.25 369.26 2185.06 ;
        RECT  368.26 1786.25 369.26 1919.52 ;
        RECT  368.26 1500.25 369.26 1545.52 ;
        RECT  368.26 1118.25 369.26 1259.52 ;
        RECT  368.26 866.25 369.26 877.52 ;
        RECT  368.26 430.12 369.26 625.52 ;
        RECT  368.26 14.9 369.26 189.52 ;
        RECT  318.26 2160.01 319.26 2185.06 ;
        RECT  318.26 1786.01 319.26 1919.76 ;
        RECT  318.26 1500.01 319.26 1545.76 ;
        RECT  318.26 1118.01 319.26 1259.76 ;
        RECT  318.26 866.01 319.26 877.76 ;
        RECT  318.26 430.01 319.26 625.76 ;
        RECT  318.26 14.9 319.26 189.76 ;
        RECT  268.26 2160.25 269.26 2185.06 ;
        RECT  268.26 1786.25 269.26 1919.52 ;
        RECT  268.26 1500.25 269.26 1545.52 ;
        RECT  268.26 1118.25 269.26 1259.52 ;
        RECT  268.26 866.25 269.26 877.52 ;
        RECT  268.26 430.12 269.26 625.52 ;
        RECT  268.26 14.9 269.26 189.52 ;
        RECT  218.26 2160.25 219.26 2185.06 ;
        RECT  218.26 1786.25 219.26 1919.52 ;
        RECT  218.26 1500.25 219.26 1545.52 ;
        RECT  218.26 1118.25 219.26 1259.52 ;
        RECT  218.26 866.25 219.26 877.52 ;
        RECT  218.26 430.12 219.26 625.52 ;
        RECT  218.26 14.9 219.26 189.52 ;
        RECT  168.26 2160.01 169.26 2185.06 ;
        RECT  168.26 1786.01 169.26 1919.76 ;
        RECT  168.26 1500.01 169.26 1545.76 ;
        RECT  168.26 1118.01 169.26 1259.76 ;
        RECT  168.26 866.01 169.26 877.76 ;
        RECT  168.26 430.01 169.26 625.76 ;
        RECT  168.26 14.9 169.26 189.76 ;
        RECT  118.26 2160.25 119.26 2185.06 ;
        RECT  118.26 1786.25 119.26 1919.52 ;
        RECT  118.26 1500.25 119.26 1545.52 ;
        RECT  118.26 1118.25 119.26 1259.52 ;
        RECT  118.26 866.25 119.26 877.52 ;
        RECT  118.26 430.12 119.26 625.52 ;
        RECT  118.26 14.9 119.26 189.52 ;
        RECT  68.26 2160.25 69.26 2185.06 ;
        RECT  68.26 1786.25 69.26 1919.52 ;
        RECT  68.26 1500.25 69.26 1545.52 ;
        RECT  68.26 1118.25 69.26 1259.52 ;
        RECT  68.26 866.25 69.26 877.52 ;
        RECT  68.26 430.12 69.26 625.52 ;
        RECT  68.26 14.9 69.26 189.52 ;
        RECT  18.26 14.9 19.26 2185.06 ;
    END
  END VGND
  OBS
    LAYER Metal1 ;
     RECT  3.215 0 1900 2200 ;
    LAYER Metal2 ;
     RECT  3.215 0 1900 2200 ;
    LAYER Metal3 ;
     RECT  3.215 0 1900 2200 ;
    LAYER Metal4 ;
     RECT  3.215 0 1900 2200 ;
    LAYER TopMetal1 ;
     RECT  3.215 0 1900 2200 ;
  END
END ino_fetch
END LIBRARY
